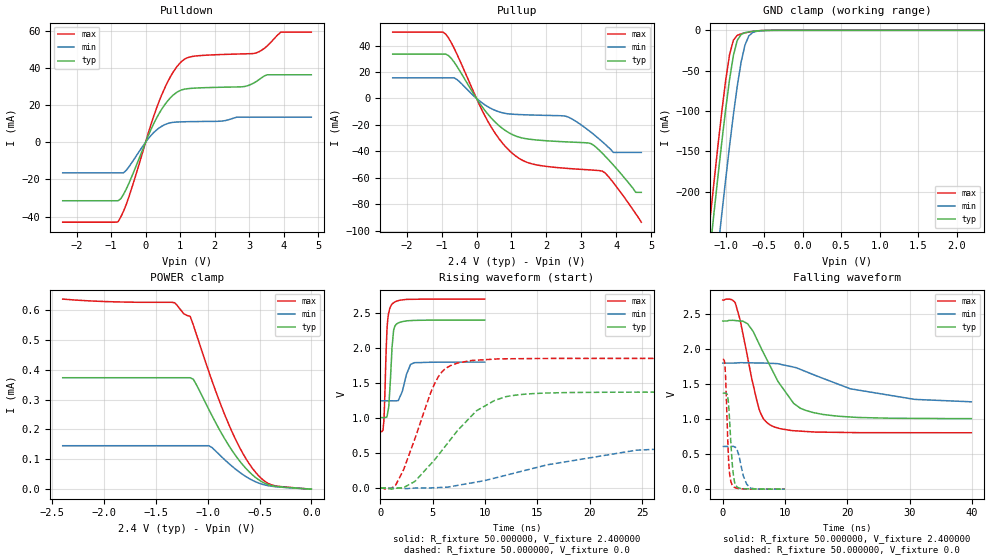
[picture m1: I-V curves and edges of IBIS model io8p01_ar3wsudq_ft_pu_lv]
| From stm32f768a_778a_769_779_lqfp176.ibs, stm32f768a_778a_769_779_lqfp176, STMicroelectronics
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|   Model io8p01_ar3wsudq_ft_pu_lv
[Model]  io8p01_ar3wsudq_ft_pu_lv
Model_type I/O
Polarity   Non-Inverting
Enable   Active-Low
Vinl =   0.720000V
Vinh =   1.680000V
Vmeas =  1.200000V
Cref =   50.000000pF
Rref =   100.000000M
Vref =   0.0V
C_comp   3.720900pF   3.684200pF   3.822900pF
[Temperature Range]   25.000000   0.125000k   -40.000000
[Pullup Reference]   2.400000V   1.800000V   2.700000V
[Pulldown Reference]   0.0V   0.0V   0.0V
[POWER Clamp Reference]   2.400000V   1.800000V   2.700000V
[GND Clamp Reference]   0.0V   0.0V   0.0V
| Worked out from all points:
|   slope of the pulldown table from 0 to 0.36 V, typ, clamps not added: 25 ohm
|   slope of the pullup table from 0 to 0.36 V, typ, clamps not added: 27.7 ohm
|   GND clamp passes 1 mA (typ) near -0.62 V on its own axis
|   rising waveform, R_fixture 50.000000, V_fixture 2.400000: 20-80 % time 330ps typ, 644ps min, 262ps max; typ from 1.01 V to 2.4 V
|   rising waveform, R_fixture 50.000000, V_fixture 0.0: 20-80 % time 4.73ns typ, 11.9ns min, 2.67ns max; typ from 0.001 V to 1.37 V
|   falling waveform, R_fixture 50.000000, V_fixture 2.400000: 20-80 % time 5.31ns typ, 12.6ns min, 2.7ns max; typ from 2.4 V to 1.01 V
|   falling waveform, R_fixture 50.000000, V_fixture 0.0: 20-80 % time 594ps typ, 1.03ns min, 462ps max; typ from 1.37 V to 0.001 V
[Pulldown]
|Voltage   I(typ)   I(min)   I(max)
-2.4V     -31.47mA   -16.45mA   -43.01mA
-800mV    -31.47mA   -16.45mA   -42.85mA
-480mV    -21.98mA   -13.17mA   -29.21mA
80mV      3.63mA     1.966mA    5.014mA
480mV     18.16mA    8.738mA    26.02mA
800mV     25.38mA    10.72mA    37.77mA
1.12V     28.53mA    11.02mA    44.6mA
2.8V      29.84mA    13.47mA    47.53mA
3.2V      32.6mA     13.47mA    48.03mA
3.52V     36.29mA    13.47mA    51.75mA
3.92V     36.29mA    13.47mA    59.26mA
4.8V      36.29mA    13.47mA    59.26mA
[Pullup]
|Voltage   I(typ)   I(min)   I(max)
-2.4V     33.5mA     15.56mA    50.21mA
-960mV    33.5mA     15.56mA    50.21mA
-560mV    24.27mA    14.3mA     33.51mA
320mV     -11.75mA   -6.207mA   -17.08mA
960mV     -26.47mA   -11.82mA   -40.02mA
1.52V     -30.88mA   -12.51mA   -49.05mA
2.56V     -32.88mA   -13.52mA   -52.9mA
3.28V     -34.25mA   -25.64mA   -54.17mA
3.6V      -41.44mA   -32.74mA   -55.02mA
3.92V     -50.46mA   -40.9mA    -63.78mA
4.56V     -71.1mA    -40.9mA    -87.26mA
4.72V     -71.1mA    -40.9mA    -93.7mA
[GND_clamp]
|Voltage   I(typ)   I(min)   I(max)
-2.4V     -1.43A     -1.515A    -1.399A
-1.25V    -315.9mA   -407.2mA   -278.2mA
-1.2V     -270.1mA   -361.3mA   -232.1mA
-1.15V    -225mA     -316mA     -186.8mA
-1.1V     -180.9mA   -271.3mA   -142.7mA
-1.05V    -138.2mA   -227.5mA   -100.5mA
-950mV    -61.14mA   -143.6mA   -30.43mA
-900mV    -31.23mA   -104.7mA   -12.14mA
-850mV    -12.49mA   -69.4mA    -6.221mA
-750mV    -2.898mA   -18.35mA   -3.18mA
-600mV    -750.2uA   -1.218mA   -738.3uA
2.35V     0A         0A         0A
[POWER_clamp]
|Voltage   I(typ)   I(min)   I(max)
-2.4V     373.1uA    145.5uA    636.5uA
-1.32V    373.1uA    145.5uA    624.2uA
-1.23V    373.1uA    145.5uA    587.2uA
-1.17V    373.1uA    145.5uA    579uA
-1.14V    368.3uA    145.5uA    550.7uA
-990mV    267.3uA    145.5uA    393.9uA
-810mV    153.6uA    90.29uA    227.7uA
-690mV    93.37uA    55.97uA    138.2uA
-570mV    48.37uA    29.94uA    70.44uA
-480mV    25.27uA    17.04uA    35.17uA
-390mV    12.49uA    10.18uA    15.16uA
0V        0A         0A         0A
[Ramp]
| variable   typ   min   max
dV/dt_r  0.82207/4.72862n   0.36540/11.89681n   1.11083/2.66726n
dV/dt_f  0.83604/5.30747n   0.32304/13.46437n   1.13706/2.70224n
R_load = 50.000000
[Rising Waveform]
R_fixture= 50.000000
V_fixture= 2.400000
V_fixture_min= 1.800000
V_fixture_max= 2.700000
|time   V(typ)   V(min)   V(max)
0s        1.007V     1.247V     805.8mV
340.3ps   1.007V     1.247V     952.4mV
640.6ps   1.02V      1.247V     2.264V
820.8ps   1.189V     1.247V     2.513V
1.081ns   1.885V     1.247V     2.619V
1.281ns   2.262V     1.246V     2.647V
1.822ns   2.365V     1.286V     2.683V
2.883ns   2.392V     1.763V     2.696V
3.263ns   2.395V     1.791V     2.697V
9.97ns    2.4V       1.8V       2.7V
[Rising Waveform]
R_fixture= 50.000000
V_fixture= 0.0
V_fixture_min= 0.0
V_fixture_max= 0.0
|time   V(typ)   V(min)   V(max)
0s        1.058mV    912.7uV    1.36mV
1.522ns   -1.796mV   978.9uV    58.52mV
3.283ns   94.32mV    755.9uV    696.3mV
5.205ns   407.6mV    5.629mV    1.497V
6.086ns   575.8mV    11.51mV    1.689V
7.367ns   820.7mV    38.96mV    1.785V
9.209ns   1.107V     87.48mV    1.827V
13.37ns   1.335V     236.1mV    1.849V
24.42ns   1.37V      541.3mV    1.852V
39.88ns   1.371V     610.2mV    1.852V
[Falling Waveform]
R_fixture= 50.000000
V_fixture= 2.400000
V_fixture_min= 1.800000
V_fixture_max= 2.700000
|time   V(typ)   V(min)   V(max)
0s        2.4V       1.8V       2.7V
2.002ns   2.407V     1.801V     2.664V
2.803ns   2.4V       1.805V     2.412V
4.004ns   2.36V      1.804V     1.877V
5.846ns   2.072V     1.801V     1.14V
7.688ns   1.744V     1.796V     913mV
11.37ns   1.226V     1.742V     834.9mV
14.49ns   1.095V     1.637V     817.6mV
20.5ns    1.031V     1.433V     808.8mV
39.88ns   1.007V     1.247V     805.8mV
[Falling Waveform]
R_fixture= 50.000000
V_fixture= 0.0
V_fixture_min= 0.0
V_fixture_max= 0.0
|time   V(typ)   V(min)   V(max)
0s        1.371V     610.2mV    1.852V
380.4ps   1.371V     610.2mV    1.736V
880.9ps   1.273V     610mV      544.5mV
1.121ns   955.6mV    609.7mV    211.5mV
1.481ns   430.2mV    610.4mV    67.59mV
1.762ns   167.4mV    610.2mV    34.19mV
2.122ns   52.66mV    594mV      18.53mV
3.323ns   8.052mV    186.9mV    5.117mV
4.484ns   4.244mV    15.81mV    2.894mV
9.97ns    1.058mV    912.7uV    1.36mV
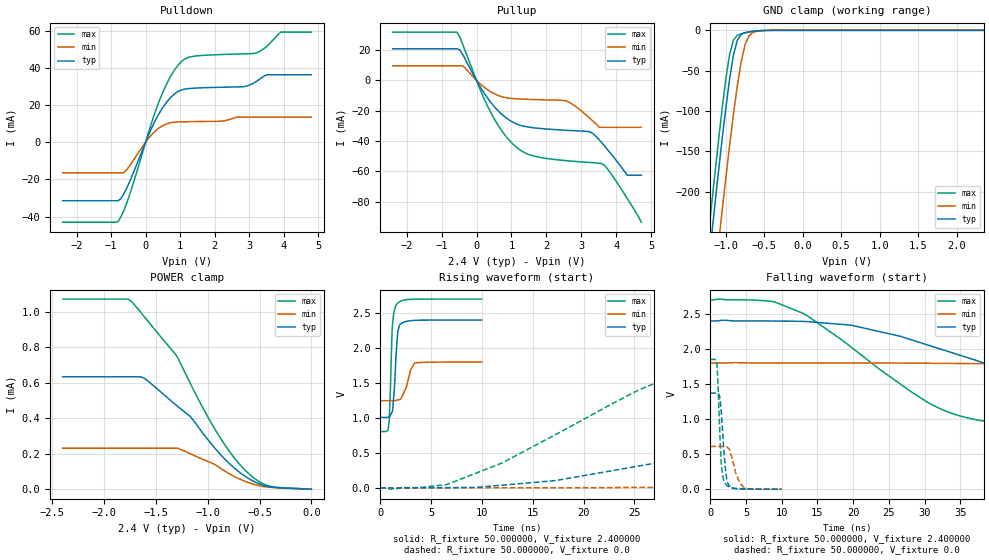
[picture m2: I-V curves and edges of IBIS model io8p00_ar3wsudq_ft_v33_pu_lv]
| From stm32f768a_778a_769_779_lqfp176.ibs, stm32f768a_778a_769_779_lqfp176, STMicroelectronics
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|   Model io8p00_ar3wsudq_ft_v33_pu_lv
[Model]  io8p00_ar3wsudq_ft_v33_pu_lv
Model_type I/O
Polarity   Non-Inverting
Enable   Active-Low
Vinl =   0.720000V
Vinh =   1.680000V
Vmeas =  1.200000V
Cref =   50.000000pF
Rref =   100.000000M
Vref =   0.0V
C_comp   3.737300pF   3.690400pF   3.817400pF
[Temperature Range]   25.000000   0.125000k   -40.000000
[Pullup Reference]   2.400000V   1.800000V   2.700000V
[Pulldown Reference]   0.0V   0.0V   0.0V
[POWER Clamp Reference]   2.400000V   1.800000V   2.700000V
[GND Clamp Reference]   0.0V   0.0V   0.0V
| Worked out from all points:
|   slope of the pulldown table from 0 to 0.36 V, typ, clamps not added: 25 ohm
|   slope of the pullup table from 0 to 0.36 V, typ, clamps not added: 27.7 ohm
|   GND clamp passes 1 mA (typ) near -0.62 V on its own axis
|   rising waveform, R_fixture 50.000000, V_fixture 2.400000: 20-80 % time 349ps typ, 697ps min, 262ps max; typ from 1.01 V to 2.4 V
|   rising waveform, R_fixture 50.000000, V_fixture 0.0: 20-80 % time 31ns typ, 81.8ns min, 14.6ns max; typ from 0.001 V to 1.37 V
|   falling waveform, R_fixture 50.000000, V_fixture 2.400000: 20-80 % time 28.8ns typ, 81.6ns min, 15.7ns max; typ from 2.4 V to 1.01 V
|   falling waveform, R_fixture 50.000000, V_fixture 0.0: 20-80 % time 599ps typ, 1.08ns min, 460ps max; typ from 1.37 V to 0.001 V
[Pulldown]
|Voltage   I(typ)   I(min)   I(max)
-2.4V     -31.47mA   -16.45mA   -43.01mA
-800mV    -31.47mA   -16.45mA   -42.85mA
-480mV    -21.98mA   -13.17mA   -29.21mA
80mV      3.63mA     1.966mA    5.014mA
480mV     18.16mA    8.738mA    26.02mA
800mV     25.38mA    10.72mA    37.77mA
1.12V     28.53mA    11.02mA    44.6mA
2.8V      29.84mA    13.47mA    47.53mA
3.2V      32.6mA     13.47mA    48.03mA
3.52V     36.3mA     13.47mA    51.75mA
3.92V     36.3mA     13.47mA    59.27mA
4.8V      36.3mA     13.47mA    59.27mA
[Pullup]
|Voltage   I(typ)   I(min)   I(max)
-2.4V     20.87mA    9.66mA     31.87mA
-560mV    20.87mA    9.66mA     31.87mA
-400mV    17.27mA    9.66mA     24.06mA
320mV     -11.75mA   -6.207mA   -17.08mA
640mV     -20.52mA   -10.1mA    -30.35mA
960mV     -26.47mA   -11.82mA   -40.02mA
1.52V     -30.88mA   -12.51mA   -49.05mA
2.56V     -32.88mA   -13.52mA   -52.9mA
3.28V     -34.25mA   -25.61mA   -54.17mA
3.6V      -41.44mA   -30.97mA   -55.02mA
4.32V     -62.54mA   -30.97mA   -77.98mA
4.72V     -62.54mA   -30.97mA   -93.5mA
[GND_clamp]
|Voltage   I(typ)   I(min)   I(max)
-2.4V     -1.437A    -1.518A    -1.411A
-1.25V    -315.9mA   -407.2mA   -278.2mA
-1.2V     -270.1mA   -361.3mA   -232.1mA
-1.15V    -225mA     -316mA     -186.8mA
-1.1V     -180.9mA   -271.3mA   -142.7mA
-1.05V    -138.2mA   -227.5mA   -100.5mA
-950mV    -61.14mA   -143.6mA   -30.43mA
-900mV    -31.23mA   -104.7mA   -12.14mA
-850mV    -12.49mA   -69.4mA    -6.221mA
-750mV    -2.898mA   -18.35mA   -3.18mA
-600mV    -750.2uA   -1.218mA   -738.3uA
2.35V     0A         0A         0A
[POWER_clamp]
|Voltage   I(typ)   I(min)   I(max)
-2.4V     634.4uA    230.9uA    1.073mA
-1.77V    634.4uA    230.9uA    1.073mA
-1.74V    634.4uA    230.9uA    1.062mA
-1.62V    628.7uA    230.9uA    979.3uA
-1.29V    467.4uA    230.9uA    743.1uA
-1.17V    410.9uA    200.6uA    599.2uA
-930mV    230.8uA    139uA      338.2uA
-780mV    138.4uA    83.46uA    204.6uA
-660mV    81.05uA    49.28uA    119.5uA
-540mV    39.7uA     25.07uA    57.27uA
-420mV    15.59uA    11.9uA     19.92uA
0V        0A         0A         0A
[Ramp]
| variable   typ   min   max
dV/dt_r  0.82201/30.92570n   0.36327/83.87425n   1.11083/14.60680n
dV/dt_f  0.83622/28.87659n   0.32652/81.83571n   1.13655/15.69998n
R_load = 50.000000
[Rising Waveform]
R_fixture= 50.000000
V_fixture= 2.400000
V_fixture_min= 1.800000
V_fixture_max= 2.700000
|time   V(typ)   V(min)   V(max)
0s        1.007V     1.247V     805.7mV
780.8ps   1.012V     1.247V     841.9mV
880.9ps   1.016V     1.247V     968.3mV
1.181ns   1.091V     1.247V     2.287V
1.381ns   1.402V     1.247V     2.533V
1.642ns   2.077V     1.254V     2.631V
1.722ns   2.228V     1.257V     2.642V
1.882ns   2.325V     1.262V     2.66V
3.383ns   2.395V     1.787V     2.698V
9.97ns    2.4V       1.8V       2.7V
[Rising Waveform]
R_fixture= 50.000000
V_fixture= 0.0
V_fixture_min= 0.0
V_fixture_max= 0.0
|time   V(typ)   V(min)   V(max)
0s        880.4uV    840.3uV    911.2uV
7.007ns   4.47mV     1.89mV     73.8mV
17.02ns   102.2mV    2.038mV    744.7mV
28.03ns   379.3mV    8.496mV    1.545V
34.53ns   558.8mV    15.84mV    1.716V
42.54ns   789.7mV    42.96mV    1.792V
59.56ns   1.173V     100.6mV    1.839V
79.58ns   1.316V     194.5mV    1.848V
153.2ns   1.369V     511.4mV    1.852V
249.2ns   1.371V     610.3mV    1.852V
[Falling Waveform]
R_fixture= 50.000000
V_fixture= 2.400000
V_fixture_min= 1.800000
V_fixture_max= 2.700000
|time   V(typ)   V(min)   V(max)
0s        2.4V       1.8V       2.7V
8.509ns   2.399V     1.8V       2.682V
13.01ns   2.395V     1.8V       2.508V
20.02ns   2.332V     1.8V       2.003V
31.03ns   2.038V     1.796V     1.204V
43.54ns   1.628V     1.776V     914.4mV
60.06ns   1.241V     1.72V      849.1mV
84.08ns   1.084V     1.587V     820.8mV
157.2ns   1.016V     1.326V     805.6mV
249.2ns   1.007V     1.247V     805.7mV
[Falling Waveform]
R_fixture= 50.000000
V_fixture= 0.0
V_fixture_min= 0.0
V_fixture_max= 0.0
|time   V(typ)   V(min)   V(max)
0s        1.371V     610.3mV    1.852V
900.9ps   1.372V     610.1mV    1.797V
1.101ns   1.368V     610mV      1.45V
1.502ns   1.152V     609.7mV    431.2mV
1.702ns   858.3mV    609.9mV    213.2mV
2.062ns   351.2mV    609.6mV    86.32mV
2.683ns   44.51mV    567.8mV    32.29mV
3.584ns   8.699mV    225.6mV    11.4mV
4.785ns   3.064mV    15.43mV    3.973mV
9.97ns    880.4uV    840.3uV    911.2uV
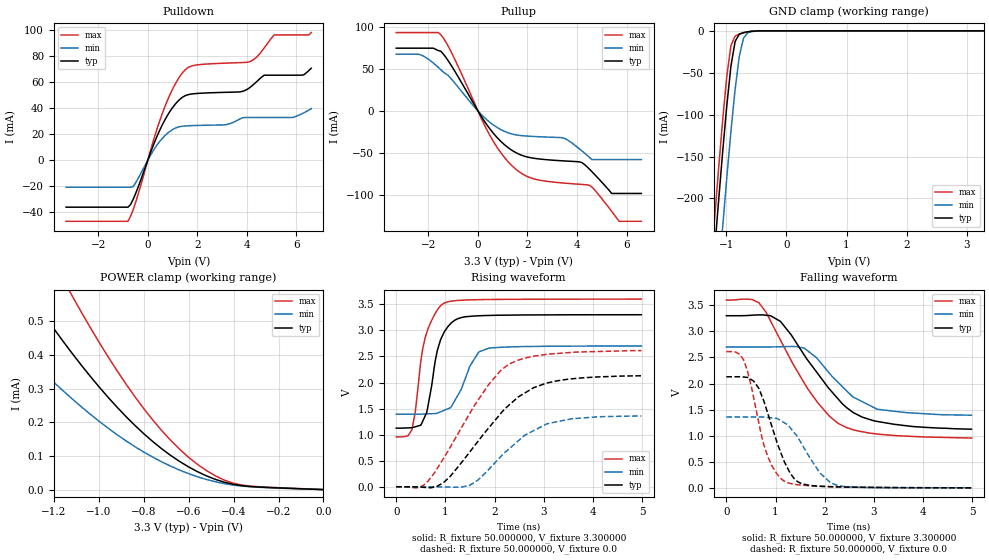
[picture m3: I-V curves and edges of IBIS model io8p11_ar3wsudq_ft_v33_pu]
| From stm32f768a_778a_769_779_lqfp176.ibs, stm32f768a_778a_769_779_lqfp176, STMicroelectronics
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|   Model io8p11_ar3wsudq_ft_v33_pu
[Model]  io8p11_ar3wsudq_ft_v33_pu
Model_type I/O
Polarity   Non-Inverting
Enable   Active-Low
Vinl =   0.990000V
Vinh =   2.310000V
Vmeas =  1.650000V
Cref =   30.000000pF
Rref =   100.000000M
Vref =   0.0V
C_comp   3.857500pF   3.760500pF   3.941700pF
[Temperature Range]   25.000000   0.125000k   -40.000000
[Pullup Reference]   3.300000V   2.700000V   3.600000V
[Pulldown Reference]   0.0V   0.0V   0.0V
[POWER Clamp Reference]   3.300000V   2.700000V   3.600000V
[GND Clamp Reference]   0.0V   0.0V   0.0V
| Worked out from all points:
|   slope of the pulldown table from 0 to 0.495 V, typ, clamps not added: 20.9 ohm
|   slope of the pullup table from 0 to 0.495 V, typ, clamps not added: 22.6 ohm
|   GND clamp passes 1 mA (typ) near -0.62 V on its own axis
|   POWER clamp passes 1 mA (typ) near -1.88 V on its own axis
|   rising waveform, R_fixture 50.000000, V_fixture 3.300000: 20-80 % time 276ps typ, 389ps min, 269ps max; typ from 1.12 V to 3.3 V
|   rising waveform, R_fixture 50.000000, V_fixture 0.0: 20-80 % time 1.16ns typ, 998ps min, 1.05ns max; typ from 0.001 V to 2.13 V
|   falling waveform, R_fixture 50.000000, V_fixture 3.300000: 20-80 % time 1.06ns typ, 878ps min, 1.03ns max; typ from 3.3 V to 1.12 V
|   falling waveform, R_fixture 50.000000, V_fixture 0.0: 20-80 % time 473ps typ, 562ps min, 410ps max; typ from 2.13 V to 0.001 V
[Pulldown]
|Voltage   I(typ)   I(min)   I(max)
-3.3V     -36.18mA   -20.77mA   -47.07mA
-800mV    -36.18mA   -20.77mA   -47.07mA
-600mV    -30.5mA    -20.52mA   -38.69mA
700mV     31.4mA     19.11mA    41.71mA
1.2V      45.15mA    25.37mA    61.75mA
1.6V      50.35mA    26.5mA     71.06mA
3.1V      52.28mA    27.26mA    74.76mA
4.1V      55.65mA    32.9mA     75.79mA
4.7V      65.5mA     32.9mA     86.49mA
5.1V      65.5mA     32.9mA     96.53mA
6.3V      65.8mA     36.47mA    96.53mA
6.6V      70.85mA    39.68mA    98.34mA
[Pullup]
|Voltage   I(typ)   I(min)   I(max)
-3.3V     74.6mA     67.42mA    93.17mA
-2.3V     74.6mA     66.59mA    93.17mA
-1.5V     71.1mA     49.01mA    90.67mA
-1V       50.41mA    35.45mA    65.35mA
500mV     -22.06mA   -14mA      -30.03mA
1.6V      -50.64mA   -28.81mA   -70.96mA
3.5V      -59.52mA   -32.72mA   -85.91mA
4.2V      -61.52mA   -47.6mA    -87.45mA
4.5V      -69.2mA    -55.15mA   -88.43mA
5.4V      -98.2mA    -57.9mA    -119.4mA
5.7V      -98.2mA    -57.9mA    -131.3mA
6.6V      -98.2mA    -57.9mA    -131.3mA
[GND_clamp]
|Voltage   I(typ)   I(min)   I(max)
-3.3V     -2.332A    -2.407A    -2.312A
-1.2V     -270.2mA   -361.4mA   -232.1mA
-1.13V    -207.3mA   -298.1mA   -169mA
-1.06V    -146.7mA   -236.2mA   -108.8mA
-990mV    -90.18mA   -176.4mA   -54.96mA
-920mV    -42.21mA   -120mA     -17.68mA
-850mV    -12.57mA   -69.47mA   -6.265mA
-780mV    -3.971mA   -30.01mA   -3.886mA
-710mV    -2.1mA     -8.615mA   -2.382mA
-640mV    -1.148mA   -2.283mA   -1.22mA
-570mV    -524uA     -821.5uA   -476.8uA
3.28V     0A         0A         0A
[POWER_clamp]
|Voltage   I(typ)   I(min)   I(max)
-3.28V    1.18mA     571.5uA    1.791mA
-3.08V    1.154mA    558.1uA    1.753mA
-1.84V    973.4uA    557.7uA    1.433mA
-1.32V    593.1uA    370.2uA    831.6uA
-1.28V    553.9uA    355.9uA    778.7uA
-1.12V    406uA      270.4uA    577.3uA
-960mV    275.2uA    183.2uA    395.9uA
-800mV    166.2uA    111.7uA    240.7uA
-680mV    101.4uA    69.6uA     146.3uA
-560mV    53.02uA    38.04uA    74.62uA
-360mV    11.49uA    10.29uA    13.1uA
0V        0A         0A         0A
[Ramp]
| variable   typ   min   max
dV/dt_r  1.26469/1.15951n   0.80727/0.99196n   1.56136/1.04842n
dV/dt_f  1.28070/1.04377n   0.77178/0.86640n   1.57114/1.02207n
R_load = 50.000000
[Rising Waveform]
R_fixture= 50.000000
V_fixture= 3.300000
V_fixture_min= 2.700000
V_fixture_max= 3.600000
|time   V(typ)   V(min)   V(max)
0s        1.125V     1.393V     955.5mV
320.3ps   1.133V     1.393V     1.096V
510.5ps   1.199V     1.394V     2.477V
650.7ps   1.574V     1.399V     3.042V
830.8ps   2.59V      1.411V     3.383V
971ps     2.96V      1.465V     3.52V
1.111ns   3.134V     1.522V     3.559V
1.682ns   3.28V      2.587V     3.589V
1.882ns   3.286V     2.659V     3.592V
4.985ns   3.3V       2.7V       3.599V
[Rising Waveform]
R_fixture= 50.000000
V_fixture= 0.0
V_fixture_min= 0.0
V_fixture_max= 0.0
|time   V(typ)   V(min)   V(max)
0s        1.299mV    1.125mV    1.756mV
550.6ps   -9.392mV   928uV      27.16mV
951ps     72.55mV    -2.714mV   528.7mV
1.491ns   662.9mV    27.15mV    1.4V
1.882ns   1.131V     332.1mV    1.964V
2.272ns   1.55V      709.6mV    2.337V
2.613ns   1.798V     987.3mV    2.466V
3.073ns   1.991V     1.211V     2.542V
3.564ns   2.07V      1.304V     2.577V
4.985ns   2.129V     1.36V      2.612V
[Falling Waveform]
R_fixture= 50.000000
V_fixture= 3.300000
V_fixture_min= 2.700000
V_fixture_max= 3.600000
|time   V(typ)   V(min)   V(max)
0s        3.3V       2.7V       3.599V
660.7ps   3.315V     2.7V       3.55V
810.8ps   3.309V     2.701V     3.363V
1.101ns   3.19V      2.705V     2.832V
1.582ns   2.549V     2.679V     2.015V
1.862ns   2.187V     2.463V     1.628V
2.272ns   1.705V     2.024V     1.237V
2.583ns   1.443V     1.74V      1.113V
3.073ns   1.273V     1.507V     1.032V
4.985ns   1.125V     1.393V     955.5mV
[Falling Waveform]
R_fixture= 50.000000
V_fixture= 0.0
V_fixture_min= 0.0
V_fixture_max= 0.0
|time   V(typ)   V(min)   V(max)
0s        2.129V     1.36V      2.612V
350.4ps   2.125V     1.359V     2.456V
510.5ps   2.073V     1.359V     1.935V
660.7ps   1.908V     1.358V     1.246V
860.9ps   1.374V     1.348V     562.4mV
1.191ns   478.8mV    1.242V     123.2mV
1.491ns   99.44mV    910mV      57.23mV
1.902ns   31.84mV    286.2mV    32.4mV
2.282ns   19.21mV    40.56mV    19.96mV
4.985ns   1.299mV    1.125mV    1.756mV
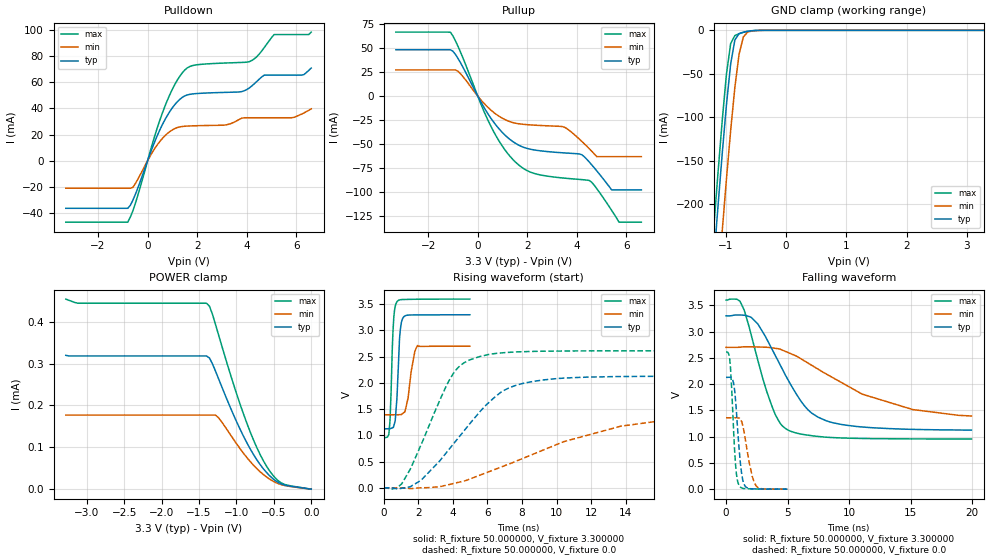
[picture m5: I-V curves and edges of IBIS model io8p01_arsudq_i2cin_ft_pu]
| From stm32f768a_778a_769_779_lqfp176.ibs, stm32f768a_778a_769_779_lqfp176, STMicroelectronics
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|   Model io8p01_arsudq_i2cin_ft_pu
[Model]  io8p01_arsudq_i2cin_ft_pu
Model_type I/O
Polarity   Non-Inverting
Enable   Active-Low
Vinl =   0.990000V
Vinh =   2.310000V
Vmeas =  1.650000V
Cref =   50.000000pF
Rref =   100.000000M
Vref =   0.0V
C_comp   2.280000pF   2.217100pF   2.355700pF
[Temperature Range]   25.000000   0.125000k   -40.000000
[Pullup Reference]   3.300000V   2.700000V   3.600000V
[Pulldown Reference]   0.0V   0.0V   0.0V
[POWER Clamp Reference]   3.300000V   2.700000V   3.600000V
[GND Clamp Reference]   0.0V   0.0V   0.0V
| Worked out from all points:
|   slope of the pulldown table from 0 to 0.495 V, typ, clamps not added: 20.9 ohm
|   slope of the pullup table from 0 to 0.495 V, typ, clamps not added: 22.6 ohm
|   GND clamp passes 1 mA (typ) near -0.62 V on its own axis
|   rising waveform, R_fixture 50.000000, V_fixture 3.300000: 20-80 % time 191ps typ, 342ps min, 164ps max; typ from 1.12 V to 3.3 V
|   rising waveform, R_fixture 50.000000, V_fixture 0.0: 20-80 % time 3.35ns typ, 6.92ns min, 2.1ns max; typ from 0.001 V to 2.13 V
|   falling waveform, R_fixture 50.000000, V_fixture 3.300000: 20-80 % time 3.18ns typ, 6.84ns min, 1.99ns max; typ from 3.3 V to 1.12 V
|   falling waveform, R_fixture 50.000000, V_fixture 0.0: 20-80 % time 434ps typ, 633ps min, 342ps max; typ from 2.13 V to 0.001 V
[Pulldown]
|Voltage   I(typ)   I(min)   I(max)
-3.3V     -36.46mA   -21.09mA   -47.09mA
-800mV    -36.46mA   -21.09mA   -47.09mA
-600mV    -30.5mA    -20.55mA   -38.69mA
700mV     31.4mA     19.11mA    41.71mA
1.2V      45.15mA    25.37mA    61.75mA
1.6V      50.35mA    26.5mA     71.06mA
3.1V      52.28mA    27.26mA    74.76mA
4.1V      55.64mA    32.87mA    75.8mA
4.7V      65.47mA    32.87mA    86.49mA
5.1V      65.47mA    32.87mA    96.56mA
6.2V      65.47mA    35.57mA    96.56mA
6.6V      70.92mA    39.71mA    98.46mA
[Pullup]
|Voltage   I(typ)   I(min)   I(max)
-3.3V     48.4mA     27.38mA    66.91mA
-1.1V     48.4mA     27.38mA    66.69mA
-700mV    35.09mA    23.45mA    46.29mA
500mV     -22.06mA   -14mA      -30.03mA
1.5V      -49.1mA    -28.3mA    -68.56mA
2.2V      -56.04mA   -30.32mA   -80.35mA
3.5V      -59.52mA   -32.65mA   -85.91mA
4.5V      -69.07mA   -55.13mA   -88.37mA
4.8V      -78.22mA   -63.4mA    -96.83mA
5.4V      -98.2mA    -63.4mA    -119.6mA
5.7V      -98.2mA    -63.4mA    -132mA
6.6V      -98.2mA    -63.4mA    -132mA
[GND_clamp]
|Voltage   I(typ)   I(min)   I(max)
-3.3V     -2.318A    -2.397A    -2.291A
-1.2V     -265.5mA   -356.1mA   -227.2mA
-1.13V    -202.6mA   -292.9mA   -164.1mA
-1.06V    -142.2mA   -231.2mA   -104.1mA
-990mV    -85.98mA   -171.6mA   -50.72mA
-920mV    -38.8mA    -115.5mA   -15.28mA
-850mV    -11.08mA   -65.6mA    -6.001mA
-780mV    -3.782mA   -27.42mA   -3.876mA
-710mV    -2.086mA   -7.69mA    -2.381mA
-640mV    -1.147mA   -2.118mA   -1.22mA
-570mV    -523.9uA   -798.4uA   -476.8uA
3.28V     0A         0A         0A
[POWER_clamp]
|Voltage   I(typ)   I(min)   I(max)
-3.28V    319.9uA    177.1uA    454.3uA
-3.12V    318.3uA    177.1uA    444.3uA
-1.4V     318.3uA    177.1uA    444.3uA
-1.36V    313.4uA    177.1uA    437.2uA
-1.28V    282.3uA    177.1uA    394.1uA
-1.24V    264.6uA    170.9uA    369.7uA
-920mV    131.9uA    89.35uA    187.2uA
-760mV    79.47uA    55.13uA    112.7uA
-640mV    48.78uA    35.04uA    68.06uA
-520mV    26.21uA    20.11uA    35uA
-400mV    12.52uA    10.81uA    14.88uA
0V        0A         0A         0A
[Ramp]
| variable   typ   min   max
dV/dt_r  1.27747/3.34646n   0.79953/6.93767n   1.56682/2.09411n
dV/dt_f  1.30134/3.17880n   0.73980/6.80234n   1.58700/1.99075n
R_load = 50.000000
[Rising Waveform]
R_fixture= 50.000000
V_fixture= 3.300000
V_fixture_min= 2.700000
V_fixture_max= 3.600000
|time   V(typ)   V(min)   V(max)
0s        1.125V     1.393V     955.6mV
300.3ps   1.127V     1.393V     1.025V
370.4ps   1.129V     1.393V     1.302V
500.5ps   1.143V     1.393V     2.661V
580.6ps   1.175V     1.393V     3.213V
760.8ps   1.678V     1.392V     3.542V
930.9ps   2.896V     1.395V     3.584V
1.161ns   3.261V     1.433V     3.591V
1.952ns   3.296V     2.713V     3.595V
4.985ns   3.3V       2.7V       3.599V
[Rising Waveform]
R_fixture= 50.000000
V_fixture= 0.0
V_fixture_min= 0.0
V_fixture_max= 0.0
|time   V(typ)   V(min)   V(max)
0s        1.447mV    1.248mV    1.816mV
1.041ns   -7.796mV   -483.2uV   74.96mV
2.162ns   143.5mV    824.5uV    820.3mV
3.844ns   758.6mV    67.51mV    2.08V
4.324ns   954.6mV    104.8mV    2.298V
4.965ns   1.215V     165.4mV    2.438V
6.767ns   1.819V     393.1mV    2.571V
8.208ns   2.002V     582.4mV    2.597V
13.69ns   2.122V     1.173V     2.612V
19.94ns   2.129V     1.36V      2.612V
[Falling Waveform]
R_fixture= 50.000000
V_fixture= 3.300000
V_fixture_min= 2.700000
V_fixture_max= 3.600000
|time   V(typ)   V(min)   V(max)
0s        3.3V       2.7V       3.599V
880.9ps   3.315V     2.7V       3.615V
1.441ns   3.311V     2.71V      3.426V
2.563ns   3.15V      2.707V     2.472V
3.684ns   2.688V     2.692V     1.609V
4.965ns   2.111V     2.608V     1.136V
6.647ns   1.514V     2.402V     1.029V
8.488ns   1.277V     2.147V     985mV
15.18ns   1.139V     1.516V     957.5mV
19.94ns   1.125V     1.393V     955.6mV
[Falling Waveform]
R_fixture= 50.000000
V_fixture= 0.0
V_fixture_min= 0.0
V_fixture_max= 0.0
|time   V(typ)   V(min)   V(max)
0s        2.129V     1.36V      2.612V
300.3ps   2.131V     1.359V     2.469V
450.5ps   2.12V      1.359V     1.945V
620.6ps   2.013V     1.359V     1.077V
830.8ps   1.515V     1.361V     319.5mV
1.041ns   823.8mV    1.354V     81.83mV
1.451ns   101.8mV    1.115V     13.34mV
1.872ns   14.37mV    520.6mV    7.459mV
2.422ns   5.905mV    72.28mV    4.505mV
4.985ns   1.447mV    1.248mV    1.816mV
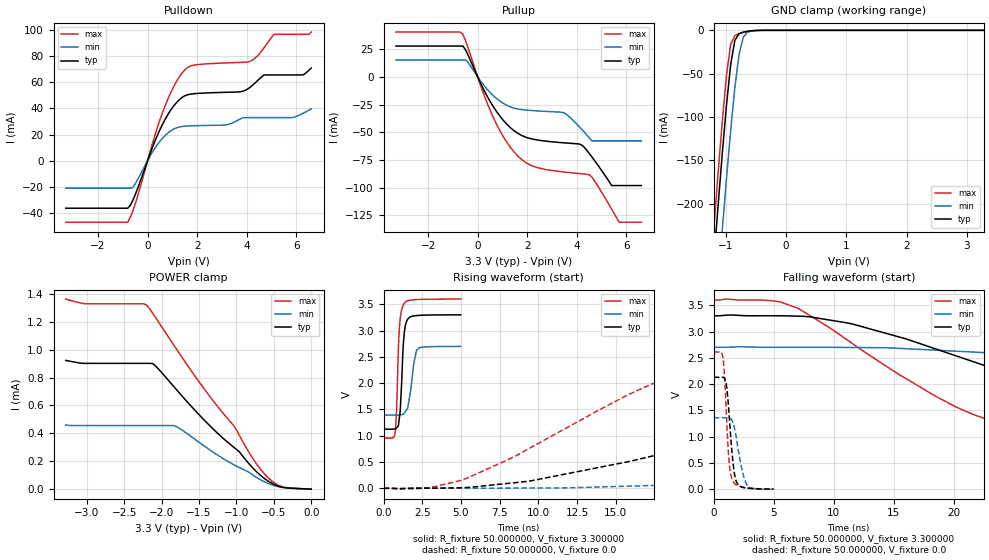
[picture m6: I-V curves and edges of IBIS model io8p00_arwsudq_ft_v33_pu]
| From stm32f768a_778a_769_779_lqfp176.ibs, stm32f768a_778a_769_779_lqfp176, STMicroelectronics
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|   Model io8p00_arwsudq_ft_v33_pu
[Model]  io8p00_arwsudq_ft_v33_pu
Model_type I/O
Polarity   Non-Inverting
Enable   Active-Low
Vinl =   0.990000V
Vinh =   2.310000V
Vmeas =  1.650000V
Cref =   50.000000pF
Rref =   100.000000M
Vref =   0.0V
C_comp   2.911600pF   2.826500pF   2.975800pF
[Temperature Range]   25.000000   0.125000k   -40.000000
[Pullup Reference]   3.300000V   2.700000V   3.600000V
[Pulldown Reference]   0.0V   0.0V   0.0V
[POWER Clamp Reference]   3.300000V   2.700000V   3.600000V
[GND Clamp Reference]   0.0V   0.0V   0.0V
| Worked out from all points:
|   slope of the pulldown table from 0 to 0.495 V, typ, clamps not added: 20.9 ohm
|   slope of the pullup table from 0 to 0.495 V, typ, clamps not added: 22.6 ohm
|   GND clamp passes 1 mA (typ) near -0.62 V on its own axis
|   rising waveform, R_fixture 50.000000, V_fixture 3.300000: 20-80 % time 219ps typ, 367ps min, 187ps max; typ from 1.12 V to 3.3 V
|   rising waveform, R_fixture 50.000000, V_fixture 0.0: 20-80 % time 19.7ns typ, 51.7ns min, 10.4ns max; typ from 0.001 V to 2.13 V
|   falling waveform, R_fixture 50.000000, V_fixture 3.300000: 20-80 % time 18.6ns typ, 38.6ns min, 11.3ns max; typ from 3.3 V to 1.12 V
|   falling waveform, R_fixture 50.000000, V_fixture 0.0: 20-80 % time 462ps typ, 672ps min, 373ps max; typ from 2.13 V to 0.001 V
[Pulldown]
|Voltage   I(typ)   I(min)   I(max)
-3.3V     -36.38mA   -21.07mA   -47.09mA
-800mV    -36.38mA   -21.07mA   -47.09mA
-600mV    -30.5mA    -20.54mA   -38.69mA
700mV     31.4mA     19.11mA    41.71mA
1.2V      45.15mA    25.37mA    61.75mA
1.6V      50.35mA    26.5mA     71.06mA
3.1V      52.28mA    27.26mA    74.76mA
4.1V      55.65mA    32.94mA    75.79mA
4.7V      65.59mA    32.94mA    86.49mA
5.1V      65.59mA    32.94mA    96.67mA
6.3V      65.82mA    36.48mA    96.67mA
6.6V      70.87mA    39.69mA    98.38mA
[Pullup]
|Voltage   I(typ)   I(min)   I(max)
-3.3V     28mA       15.42mA    40.61mA
-700mV    28mA       15.42mA    40.61mA
-400mV    20.3mA     13.47mA    26.92mA
600mV     -25.77mA   -16.23mA   -35.13mA
1.6V      -50.64mA   -28.8mA    -70.96mA
2.3V      -56.49mA   -30.48mA   -81.16mA
3.5V      -59.52mA   -32.65mA   -85.91mA
4.2V      -61.45mA   -47.47mA   -87.45mA
4.5V      -69.09mA   -55.01mA   -88.4mA
5.4V      -98.1mA    -57.7mA    -119.3mA
5.7V      -98.1mA    -57.7mA    -131.2mA
6.6V      -98.1mA    -57.7mA    -131.2mA
[GND_clamp]
|Voltage   I(typ)   I(min)   I(max)
-3.3V     -2.321A    -2.397A    -2.298A
-1.2V     -266.4mA   -356.3mA   -229.4mA
-1.13V    -203.6mA   -293.1mA   -166.3mA
-1.06V    -143.2mA   -231.4mA   -106.2mA
-990mV    -86.95mA   -171.8mA   -52.65mA
-920mV    -39.66mA   -115.8mA   -16.36mA
-850mV    -11.49mA   -65.84mA   -6.11mA
-780mV    -3.834mA   -27.59mA   -3.88mA
-710mV    -2.09mA    -7.753mA   -2.381mA
-640mV    -1.147mA   -2.129mA   -1.22mA
-570mV    -523.9uA   -800uA     -476.8uA
3.28V     0A         0A         0A
[POWER_clamp]
|Voltage   I(typ)   I(min)   I(max)
-3.28V    922.4uA    459.4uA    1.362mA
-3.04V    901.4uA    455.8uA    1.329mA
-2.2V     901.4uA    455.8uA    1.319mA
-2.08V    882.2uA    455.8uA    1.23mA
-1.8V     712.4uA    448.4uA    1.003mA
-1.4V     478.6uA    298uA      696.5uA
-1.04V    302.3uA    176.6uA    458.6uA
-800mV    163uA      108.7uA    236.3uA
-640mV    82.53uA    56.82uA    118.4uA
-520mV    40.35uA    29.6uA     55.89uA
-400mV    15.52uA    13.26uA    18.69uA
0V        0A         0A         0A
[Ramp]
| variable   typ   min   max
dV/dt_r  1.27729/19.66632n   0.81669/51.90389n   1.56688/10.39629n
dV/dt_f  1.30554/18.56173n   0.78450/38.78000n   1.58713/11.31272n
R_load = 50.000000
[Rising Waveform]
R_fixture= 50.000000
V_fixture= 3.300000
V_fixture_min= 2.700000
V_fixture_max= 3.600000
|time   V(typ)   V(min)   V(max)
0s        1.125V     1.393V     954.7mV
760.8ps   1.133V     1.393V     1.094V
840.8ps   1.154V     1.393V     1.534V
951ps     1.189V     1.393V     2.649V
1.011ns   1.327V     1.395V     3.029V
1.071ns   1.471V     1.398V     3.229V
1.301ns   2.851V     1.419V     3.508V
1.552ns   3.215V     1.523V     3.566V
2.132ns   3.286V     2.628V     3.59V
4.985ns   3.3V       2.7V       3.6V
[Rising Waveform]
R_fixture= 50.000000
V_fixture= 0.0
V_fixture_min= 0.0
V_fixture_max= 0.0
|time   V(typ)   V(min)   V(max)
0s        1.089mV    1.043mV    1.137mV
3.003ns   3.647mV    2.472mV    13.9mV
5.506ns   17.72mV    2.828mV    208.6mV
19.02ns   730mV      66.65mV    2.162V
30.53ns   1.503V     233.5mV    2.53V
37.54ns   1.836V     348.4mV    2.568V
45.55ns   1.985V     497.5mV    2.597V
72.07ns   2.103V     973.7mV    2.612V
96.6ns    2.122V     1.196V     2.613V
249.2ns   2.13V      1.36V      2.613V
[Falling Waveform]
R_fixture= 50.000000
V_fixture= 3.300000
V_fixture_min= 2.700000
V_fixture_max= 3.600000
|time   V(typ)   V(min)   V(max)
0s        3.3V       2.7V       3.6V
7.007ns   3.292V     2.7V       3.444V
11.51ns   3.146V     2.697V     2.778V
18.52ns   2.667V     2.645V     1.766V
22.52ns   2.358V     2.599V     1.349V
34.03ns   1.585V     2.37V      1.05V
49.05ns   1.251V     2.009V     990.6mV
65.07ns   1.18V      1.698V     966.3mV
86.59ns   1.148V     1.526V     958.5mV
249.2ns   1.125V     1.393V     954.7mV
[Falling Waveform]
R_fixture= 50.000000
V_fixture= 0.0
V_fixture_min= 0.0
V_fixture_max= 0.0
|time   V(typ)   V(min)   V(max)
0s        2.13V      1.36V      2.613V
640.6ps   2.13V      1.36V      2.603V
790.8ps   2.126V     1.359V     2.464V
1.001ns   2.048V     1.359V     1.673V
1.221ns   1.593V     1.357V     692.2mV
1.361ns   1.157V     1.346V     348.1mV
1.552ns   624.9mV    1.291V     174.2mV
1.902ns   137.2mV    945.6mV    78.85mV
2.713ns   22.78mV    103.4mV    27.58mV
4.985ns   1.089mV    1.043mV    1.137mV
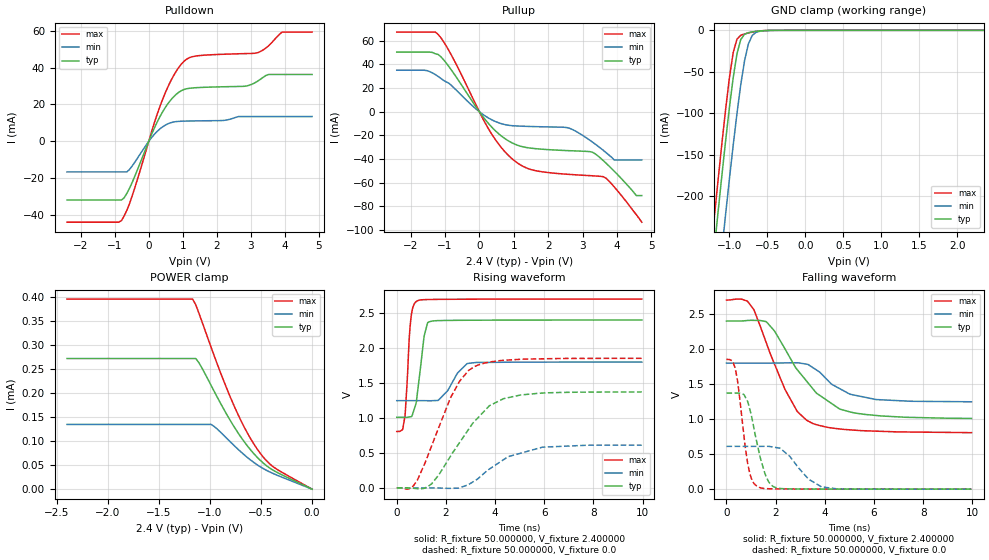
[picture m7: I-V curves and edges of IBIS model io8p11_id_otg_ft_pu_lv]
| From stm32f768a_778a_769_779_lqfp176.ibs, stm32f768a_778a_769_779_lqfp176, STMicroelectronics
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|   Model io8p11_id_otg_ft_pu_lv
[Model]  io8p11_id_otg_ft_pu_lv
Model_type I/O
Polarity   Non-Inverting
Enable   Active-Low
Vinl =   0.720000V
Vinh =   1.680000V
Vmeas =  1.200000V
Cref =   30.000000pF
Rref =   100.000000M
Vref =   0.0V
C_comp   2.229800pF   2.169700pF   2.325100pF
[Temperature Range]   25.000000   0.125000k   -40.000000
[Pullup Reference]   2.400000V   1.800000V   2.700000V
[Pulldown Reference]   0.0V   0.0V   0.0V
[POWER Clamp Reference]   2.400000V   1.800000V   2.700000V
[GND Clamp Reference]   0.0V   0.0V   0.0V
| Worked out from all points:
|   slope of the pulldown table from 0 to 0.36 V, typ, clamps not added: 25 ohm
|   slope of the pullup table from 0 to 0.36 V, typ, clamps not added: 27.7 ohm
|   GND clamp passes 1 mA (typ) near -0.62 V on its own axis
|   rising waveform, R_fixture 50.000000, V_fixture 2.400000: 20-80 % time 281ps typ, 622ps min, 182ps max; typ from 1.01 V to 2.4 V
|   rising waveform, R_fixture 50.000000, V_fixture 0.0: 20-80 % time 1.69ns typ, 1.7ns min, 1.32ns max; typ from 0.004 V to 1.37 V
|   falling waveform, R_fixture 50.000000, V_fixture 2.400000: 20-80 % time 1.83ns typ, 1.3ns min, 1.38ns max; typ from 2.4 V to 1.01 V
|   falling waveform, R_fixture 50.000000, V_fixture 0.0: 20-80 % time 539ps typ, 931ps min, 387ps max; typ from 1.37 V to 0.004 V
[Pulldown]
|Voltage   I(typ)   I(min)   I(max)
-2.4V     -31.73mA   -16.51mA   -43.74mA
-800mV    -31.73mA   -16.51mA   -42.87mA
-480mV    -21.97mA   -13.17mA   -29.21mA
80mV      3.63mA     1.966mA    5.014mA
480mV     18.15mA    8.737mA    26.02mA
800mV     25.37mA    10.72mA    37.77mA
1.12V     28.53mA    11.02mA    44.6mA
2.8V      29.84mA    13.46mA    47.53mA
3.2V      32.6mA     13.46mA    48.03mA
3.52V     36.23mA    13.46mA    51.75mA
3.92V     36.23mA    13.46mA    59.19mA
4.8V      36.23mA    13.46mA    59.19mA
[Pullup]
|Voltage   I(typ)   I(min)   I(max)
-2.4V     50.44mA    35.08mA    67.34mA
-1.52V    50.44mA    34.74mA    67.34mA
-1.2V     48.48mA    29.88mA    65.49mA
320mV     -11.75mA   -6.206mA   -17.08mA
1.04V     -27.53mA   -11.97mA   -41.9mA
1.6V      -31.13mA   -12.57mA   -49.62mA
2.56V     -32.87mA   -13.48mA   -52.89mA
3.28V     -34.17mA   -25.51mA   -54.16mA
3.6V      -41.29mA   -32.6mA    -54.95mA
3.92V     -50.3mA    -40.8mA    -63.6mA
4.56V     -70.9mA    -40.8mA    -87.05mA
4.72V     -70.9mA    -40.8mA    -93.4mA
[GND_clamp]
|Voltage   I(typ)   I(min)   I(max)
-2.4V     -1.424A    -1.508A    -1.393A
-1.25V    -311.2mA   -401.9mA   -273.3mA
-1.2V     -265.4mA   -356.1mA   -227.2mA
-1.15V    -220.4mA   -310.8mA   -181.9mA
-1.1V     -176.3mA   -266.2mA   -137.9mA
-1.05V    -133.8mA   -222.5mA   -95.88mA
-950mV    -57.31mA   -138.9mA   -26.99mA
-900mV    -28.28mA   -100.4mA   -10.61mA
-850mV    -11.02mA   -65.55mA   -5.978mA
-750mV    -2.847mA   -16.51mA   -3.192mA
-600mV    -755.4uA   -1.17mA    -743.6uA
2.35V     0A         0A         0A
[POWER_clamp]
|Voltage   I(typ)   I(min)   I(max)
-2.4V     272.5uA    135uA      396.5uA
-1.17V    272.5uA    135uA      396.5uA
-1.14V    272.5uA    135uA      384.7uA
-1.11V    264.2uA    135uA      368uA
-990mV    216.8uA    135uA      296.5uA
-870mV    168.8uA    113.3uA    228.2uA
-750mV    125.6uA    88.19uA    167.1uA
-660mV    97.6uA     70.82uA    127.5uA
-570mV    73.91uA    55.62uA    94.12uA
-480mV    54.73uA    43.14uA    67.37uA
-390mV    40.65uA    33.48uA    48.23uA
0V        0A         0A         0A
[Ramp]
| variable   typ   min   max
dV/dt_r  0.82153/1.68911n   0.36481/1.68583n   1.11056/1.32240n
dV/dt_f  0.82950/1.81907n   0.33138/1.30083n   1.13305/1.37845n
R_load = 50.000000
[Rising Waveform]
R_fixture= 50.000000
V_fixture= 2.400000
V_fixture_min= 1.800000
V_fixture_max= 2.700000
|time   V(typ)   V(min)   V(max)
0s        1.011V     1.249V     809.2mV
240.2ps   1.011V     1.249V     836.9mV
340.3ps   1.011V     1.249V     1.043V
500.5ps   1.015V     1.249V     2.09V
580.6ps   1.02V      1.249V     2.436V
840.8ps   1.358V     1.249V     2.674V
1.121ns   2.181V     1.249V     2.691V
1.361ns   2.379V     1.248V     2.693V
2.883ns   2.397V     1.78V      2.697V
9.97ns    2.4V       1.8V       2.699V
[Rising Waveform]
R_fixture= 50.000000
V_fixture= 0.0
V_fixture_min= 0.0
V_fixture_max= 0.0
|time   V(typ)   V(min)   V(max)
0s        3.745mV    3.286mV    4.323mV
680.7ps   -1.614mV   3.272mV    34.09mV
1.421ns   62.42mV    3.32mV     605.2mV
2.202ns   464.2mV    -2.565mV   1.3V
2.563ns   653.8mV    7.148mV    1.53V
3.163ns   952.8mV    102.8mV    1.735V
3.764ns   1.174V     271.4mV    1.799V
4.344ns   1.277V     406mV      1.825V
5.926ns   1.357V     585mV      1.846V
9.97ns    1.373V     613.5mV    1.853V
[Falling Waveform]
R_fixture= 50.000000
V_fixture= 2.400000
V_fixture_min= 1.800000
V_fixture_max= 2.700000
|time   V(typ)   V(min)   V(max)
0s        2.4V       1.8V       2.699V
620.6ps   2.401V     1.8V       2.711V
1.101ns   2.41V      1.8V       2.569V
1.622ns   2.391V     1.8V       2.089V
2.382ns   2.003V     1.803V     1.424V
2.883ns   1.706V     1.805V     1.11V
3.283ns   1.534V     1.784V     981.5mV
3.664ns   1.372V     1.702V     922.8mV
5.065ns   1.101V     1.354V     848mV
9.97ns    1.011V     1.249V     809.2mV
[Falling Waveform]
R_fixture= 50.000000
V_fixture= 0.0
V_fixture_min= 0.0
V_fixture_max= 0.0
|time   V(typ)   V(min)   V(max)
0s        1.373V     613.5mV    1.853V
360.4ps   1.373V     613.5mV    1.721V
460.5ps   1.373V     613.5mV    1.526V
720.7ps   1.348V     613.4mV    737.1mV
961ps     1.128V     613.2mV    212.4mV
1.301ns   568.4mV    613.2mV    34.17mV
1.702ns   117.8mV    614.3mV    9.754mV
2.102ns   17.12mV    592.2mV    7.105mV
3.884ns   4.994mV    34.37mV    5.145mV
9.97ns    3.745mV    3.286mV    4.323mV
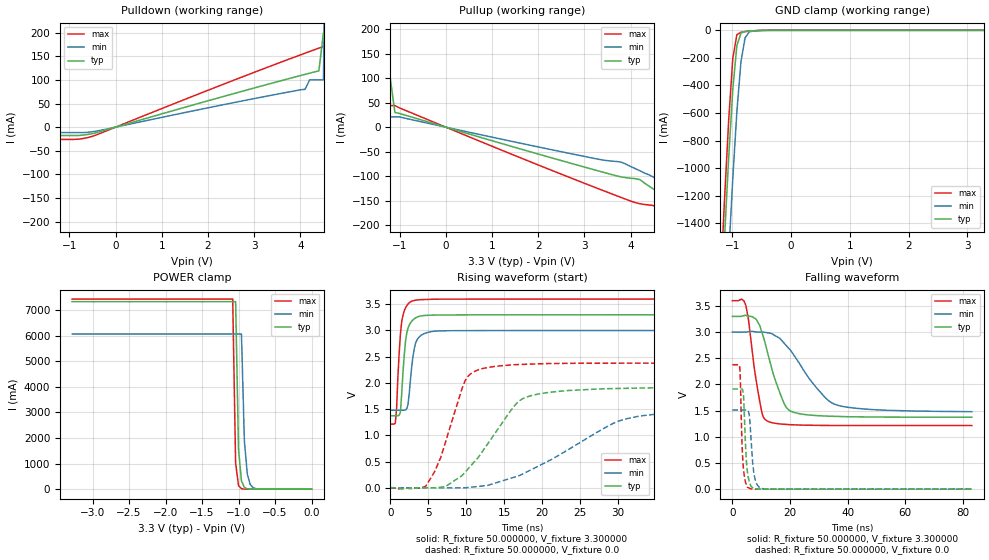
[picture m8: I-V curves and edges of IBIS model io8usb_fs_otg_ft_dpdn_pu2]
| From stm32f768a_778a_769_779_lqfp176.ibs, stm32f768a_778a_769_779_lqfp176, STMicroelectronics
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|   Model io8usb_fs_otg_ft_dpdn_pu2
[Model]  io8usb_fs_otg_ft_dpdn_pu2
Model_type I/O
Polarity   Non-Inverting
Enable   Active-Low
Vinl =   0.990000V
Vinh =   2.310000V
Vmeas =  1.650000V
Cref =   50.000000pF
Rref =   100.000000M
Vref =   0.0V
C_comp   8.255900pF   7.991100pF   8.650600pF
[Temperature Range]   25.000000   0.125000k   -40.000000
[Pullup Reference]   3.300000V   3.000000V   3.600000V
[Pulldown Reference]   0.0V   0.0V   0.0V
[POWER Clamp Reference]   3.300000V   3.000000V   3.600000V
[GND Clamp Reference]   0.0V   0.0V   0.0V
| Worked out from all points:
|   slope of the pulldown table from 0 to 0.495 V, typ, clamps not added: 35.4 ohm
|   slope of the pullup table from 0 to 0.495 V, typ, clamps not added: 36 ohm
|   GND clamp passes 1 mA (typ) near -0.52 V on its own axis
|   POWER clamp passes 1 mA (typ) near -0.81 V on its own axis
|   rising waveform, R_fixture 50.000000, V_fixture 3.300000: 20-80 % time 643ps typ, 746ps min, 588ps max; typ from 1.37 V to 3.3 V
|   rising waveform, R_fixture 50.000000, V_fixture 0.0: 20-80 % time 5.81ns typ, 11.1ns min, 3.15ns max; typ from 0 V to 1.91 V
|   falling waveform, R_fixture 50.000000, V_fixture 3.300000: 20-80 % time 6.32ns typ, 12.2ns min, 3.61ns max; typ from 3.3 V to 1.37 V
|   falling waveform, R_fixture 50.000000, V_fixture 0.0: 20-80 % time 1.03ns typ, 1.29ns min, 862ps max; typ from 1.91 V to 0 V
[Pulldown]
|Voltage   I(typ)   I(min)   I(max)
-3.3V     -181mA     -11.57mA   -221mA
-3.2V     -137mA     -11.57mA   -216mA
-2.9V     -124mA     -11.57mA   -200mA
-2.8V     -17.71mA   -11.57mA   -25.94mA
-600mV    -15.43mA   -10.85mA   -22.06mA
4.1V      111.6mA    80mA       156.4mA
4.4V      119mA      100mA      167.2mA
4.5V      200mA      100mA      170.7mA
4.6V      200mA      1A         174.2mA
4.8V      1A         1A         200mA
5.4V      1A         1A         1A
6.6V      1A         1A         1A
[Pullup]
|Voltage   I(typ)   I(min)   I(max)
-3.3V     1A         1A         1A
-1.9V     1A         1A         1A
-1.8V     100mA      1A         1A
-1.7V     100mA      1A         100mA
-1.6V     100mA      1A         100mA
-1.5V     100mA      21mA       100mA
-1.3V     100mA      21mA       100mA
-1.2V     100mA      21mA       44mA
-1.1V     30mA       21mA       44mA
4.2V      -107.2mA   -89.1mA    -156.5mA
5V        -156.8mA   -125mA     -203.2mA
6.6V      -223mA     -162mA     -321mA
[GND_clamp]
|Voltage   I(typ)   I(min)   I(max)
-3.3V     -9.433A    -9.435A    -9.911A
-1.2V     -2.116A    -2.846A    -1.847A
-1.13V    -1.505A    -2.23A     -1.23A
-1.06V    -930.4mA   -1.637A    -658.9mA
-990mV    -432.7mA   -1.08A     -207.3mA
-920mV    -110.5mA   -590.3mA   -31.59mA
-850mV    -19.84mA   -226.8mA   -13.66mA
-780mV    -8.32mA    -54.05mA   -9.516mA
-710mV    -5.29mA    -11.97mA   -6.271mA
-640mV    -3.236mA   -4.296mA   -3.584mA
3.28V     0A         0A         0A
[POWER_clamp]
|Voltage   I(typ)   I(min)   I(max)
-3.28V    7.328A     6.064A     7.43A
-1.08V    7.328A     6.064A     7.43A
-1.04V    7.328A     6.064A     1.015A
-1V       1.545A     6.064A     138.6mA
-960mV    325.6mA    6.064A     18.93mA
-920mV    68.64mA    1.89A      2.585mA
-880mV    14.47mA    589mA      353uA
-840mV    3.05mA     183.6mA    105.9uA
-800mV    642.9uA    57.21mA    105.9uA
-720mV    28.59uA    5.557mA    105.9uA
0V        0A         0A         0A
[Ramp]
| variable   typ   min   max
dV/dt_r  1.14807/5.79931n   0.90697/11.11583n   1.42586/3.14175n
dV/dt_f  1.15530/6.31678n   0.91044/12.20870n   1.43058/3.60437n
R_load = 50.000000
[Rising Waveform]
R_fixture= 50.000000
V_fixture= 3.300000
V_fixture_min= 3.000000
V_fixture_max= 3.600000
|time   V(typ)   V(min)   V(max)
0s        1.374V     1.479V     1.215V
667.3ps   1.374V     1.479V     1.235V
834.2ps   1.374V     1.479V     1.52V
1.001ns   1.374V     1.479V     2.104V
1.335ns   1.444V     1.479V     2.93V
1.668ns   2.192V     1.479V     3.29V
2.169ns   2.951V     1.508V     3.472V
3.337ns   3.24V      2.762V     3.578V
6.673ns   3.295V     2.993V     3.598V
83.08ns   3.3V       3V         3.6V
[Rising Waveform]
R_fixture= 50.000000
V_fixture= 0.0
V_fixture_min= 0.0
V_fixture_max= 0.0
|time   V(typ)   V(min)   V(max)
0s        158.5uV    83.46uV    305.9uV
4.671ns   -1.871mV   -1.413mV   29.69mV
6.673ns   11.2mV     -667.9uV   587.9mV
10.01ns   321.3mV    942.2uV    2.082V
12.85ns   838.7mV    45.69mV    2.294V
16.35ns   1.56V      202.4mV    2.348V
17.85ns   1.724V     291.9mV    2.356V
29.36ns   1.892V     1.228V     2.377V
33.37ns   1.903V     1.376V     2.377V
83.08ns   1.914V     1.512V     2.377V
[Falling Waveform]
R_fixture= 50.000000
V_fixture= 3.300000
V_fixture_min= 3.000000
V_fixture_max= 3.600000
|time   V(typ)   V(min)   V(max)
0s        3.3V       3V         3.6V
4.671ns   3.321V     3V         3.511V
9.676ns   3.095V     3V         1.623V
10.68ns   2.921V     2.999V     1.386V
12.18ns   2.615V     2.987V     1.3V
17.68ns   1.671V     2.805V     1.241V
21.52ns   1.464V     2.545V     1.229V
29.2ns    1.406V     1.937V     1.219V
36.04ns   1.39V      1.611V     1.216V
83.08ns   1.374V     1.479V     1.215V
[Falling Waveform]
R_fixture= 50.000000
V_fixture= 0.0
V_fixture_min= 0.0
V_fixture_max= 0.0
|time   V(typ)   V(min)   V(max)
0s        1.914V     1.512V     2.377V
2.503ns   1.914V     1.512V     2.349V
2.669ns   1.914V     1.512V     2.257V
3.337ns   1.916V     1.512V     889.9mV
3.67ns    1.875V     1.512V     513.2mV
4.838ns   560.2mV    1.512V     91.38mV
6.173ns   95.96mV    1.222V     10.07mV
7.508ns   13mV       292.5mV    2.821mV
9.676ns   2.221mV    20.28mV    959.5uV
83.08ns   158.5uV    83.46uV    305.9uV
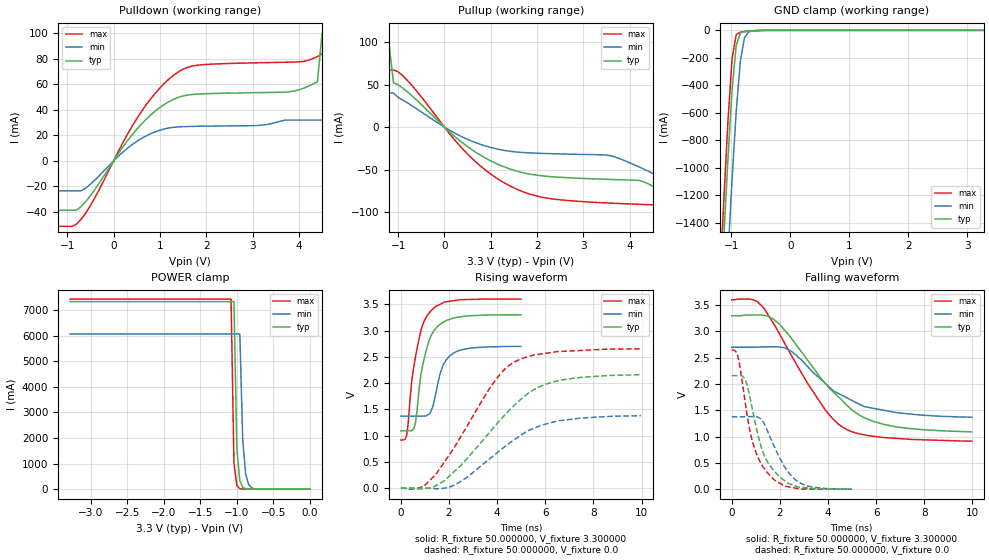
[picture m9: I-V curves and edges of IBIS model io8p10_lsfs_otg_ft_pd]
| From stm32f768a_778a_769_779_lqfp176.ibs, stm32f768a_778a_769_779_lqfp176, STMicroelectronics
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|   Model io8p10_lsfs_otg_ft_pd
[Model]  io8p10_lsfs_otg_ft_pd
Model_type I/O
Polarity   Non-Inverting
Enable   Active-Low
Vinl =   0.990000V
Vinh =   2.310000V
Vmeas =  1.650000V
Cref =   40.000000pF
Rref =   100.000000M
Vref =   0.0V
C_comp   8.196500pF   7.968500pF   8.492600pF
[Temperature Range]   25.000000   0.125000k   -40.000000
[Pullup Reference]   3.300000V   2.700000V   3.600000V
[Pulldown Reference]   0.0V   0.0V   0.0V
[POWER Clamp Reference]   3.300000V   2.700000V   3.600000V
[GND Clamp Reference]   0.0V   0.0V   0.0V
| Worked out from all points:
|   slope of the pulldown table from 0 to 0.495 V, typ, clamps not added: 20.1 ohm
|   slope of the pullup table from 0 to 0.495 V, typ, clamps not added: 21.8 ohm
|   GND clamp passes 1 mA (typ) near -0.52 V on its own axis
|   POWER clamp passes 1 mA (typ) near -0.81 V on its own axis
|   rising waveform, R_fixture 50.000000, V_fixture 3.300000: 20-80 % time 529ps typ, 501ps min, 532ps max; typ from 1.09 V to 3.3 V
|   rising waveform, R_fixture 50.000000, V_fixture 0.0: 20-80 % time 2.59ns typ, 2.4ns min, 2.18ns max; typ from 0 V to 2.16 V
|   falling waveform, R_fixture 50.000000, V_fixture 3.300000: 20-80 % time 2.44ns typ, 2.27ns min, 2.13ns max; typ from 3.3 V to 1.09 V
|   falling waveform, R_fixture 50.000000, V_fixture 0.0: 20-80 % time 846ps typ, 950ps min, 755ps max; typ from 2.16 V to 0 V
[Pulldown]
|Voltage   I(typ)   I(min)   I(max)
-3.3V     -38.65mA   -23.43mA   -51.3mA
-800mV    -38.65mA   -23.43mA   -49.55mA
600mV     28.88mA    17.56mA    38.65mA
1.4V      49.88mA    26.66mA    69.84mA
4.1V      56.96mA    32mA       77.99mA
4.4V      62mA       32mA       81.8mA
4.5V      100mA      32mA       83.9mA
4.7V      100mA      32mA       89mA
4.8V      100mA      32mA       100mA
5.1V      100mA      32mA       100mA
5.2V      1A         1A         100mA
6.6V      1A         1A         1A
[Pullup]
|Voltage   I(typ)   I(min)   I(max)
-3.3V     100mA      1A         67mA
-1.6V     100mA      1A         67mA
-1.5V     100mA      40mA       67mA
-1.2V     100mA      40mA       67mA
-1.1V     52mA       40mA       67mA
800mV     -33.66mA   -20.62mA   -46.63mA
2V        -56.45mA   -30.57mA   -80.98mA
3.5V      -61.24mA   -32.71mA   -88.93mA
4.2V      -62.54mA   -46.6mA    -90.53mA
4.9V      -81.9mA    -65mA      -102.4mA
5.5V      -103mA     -65mA      -126.2mA
6.6V      -103mA     -65mA      -139mA
[GND_clamp]
|Voltage   I(typ)   I(min)   I(max)
-3.3V     -9.479A    -9.465A    -9.974A
-1.2V     -2.125A    -2.854A    -1.857A
-1.13V    -1.511A    -2.236A    -1.236A
-1.06V    -933.3mA   -1.641A    -660.9mA
-990mV    -433.3mA   -1.082A    -207mA
-920mV    -110.3mA   -591mA     -31.46mA
-850mV    -19.8mA    -226.8mA   -13.66mA
-780mV    -8.323mA   -53.94mA   -9.521mA
-710mV    -5.297mA   -11.95mA   -6.277mA
-640mV    -3.244mA   -4.292mA   -3.591mA
3.28V     81.28uA    57.87uA    93.98uA
[POWER_clamp]
|Voltage   I(typ)   I(min)   I(max)
-3.28V    7.328A     6.064A     7.43A
-1.08V    7.328A     6.064A     7.43A
-1.04V    7.328A     6.064A     1.015A
-1V       1.545A     6.064A     138.6mA
-960mV    325.6mA    6.064A     18.93mA
-920mV    68.64mA    1.89A      2.585mA
-880mV    14.47mA    589mA      353uA
-840mV    3.05mA     183.6mA    105.2uA
-800mV    642.9uA    57.21mA    105.2uA
-720mV    28.59uA    5.557mA    105.2uA
0V        0A         0A         0A
[Ramp]
| variable   typ   min   max
dV/dt_r  1.28393/2.58462n   0.82050/2.38831n   1.58725/2.18727n
dV/dt_f  1.30050/2.41767n   0.78300/2.25179n   1.59746/2.12518n
R_load = 50.000000
[Rising Waveform]
R_fixture= 50.000000
V_fixture= 3.300000
V_fixture_min= 2.700000
V_fixture_max= 3.600000
|time   V(typ)   V(min)   V(max)
0s        1.09V      1.369V     914.2mV
250.2ps   1.09V      1.369V     1.024V
460.5ps   1.099V     1.369V     2.067V
540.5ps   1.138V     1.369V     2.319V
610.6ps   1.26V      1.369V     2.506V
900.9ps   2.326V     1.37V      3.1V
1.251ns   2.897V     1.471V     3.375V
1.752ns   3.158V     2.339V     3.527V
2.142ns   3.231V     2.557V     3.564V
4.985ns   3.299V     2.699V     3.599V
[Rising Waveform]
R_fixture= 50.000000
V_fixture= 0.0
V_fixture_min= 0.0
V_fixture_max= 0.0
|time   V(typ)   V(min)   V(max)
0s        34.9uV     19.61uV    -14.06uV
760.8ps   -17.13mV   32.35uV    1.998mV
1.441ns   43.9mV     -12.78mV   254mV
2.242ns   325.6mV    58.2mV     790.5mV
3.704ns   1.071V     562.9mV    1.909V
4.224ns   1.345V     756.3mV    2.22V
4.705ns   1.571V     918mV      2.398V
5.526ns   1.874V     1.138V     2.533V
6.466ns   2.036V     1.273V     2.597V
9.97ns    2.159V     1.378V     2.651V
[Falling Waveform]
R_fixture= 50.000000
V_fixture= 3.300000
V_fixture_min= 2.700000
V_fixture_max= 3.600000
|time   V(typ)   V(min)   V(max)
0s        3.299V     2.699V     3.599V
840.8ps   3.313V     2.699V     3.61V
1.341ns   3.305V     2.708V     3.441V
1.982ns   3.138V     2.703V     2.956V
2.543ns   2.829V     2.602V     2.491V
3.904ns   2.003V     2.004V     1.498V
4.625ns   1.67V      1.775V     1.175V
5.285ns   1.415V     1.62V      1.054V
6.326ns   1.231V     1.5V       981.5mV
9.97ns    1.09V      1.369V     914.2mV
[Falling Waveform]
R_fixture= 50.000000
V_fixture= 0.0
V_fixture_min= 0.0
V_fixture_max= 0.0
|time   V(typ)   V(min)   V(max)
0s        2.159V     1.378V     2.651V
250.2ps   2.161V     1.378V     2.534V
580.6ps   2.062V     1.378V     1.591V
750.8ps   1.763V     1.379V     1.119V
961ps     1.296V     1.378V     756.1mV
1.231ns   793.9mV    1.324V     477.8mV
1.522ns   494.6mV    1.068V     294mV
2.192ns   163.3mV    427.6mV    59.33mV
2.763ns   43.53mV    140.5mV    12.38mV
4.985ns   34.9uV     19.61uV    -14.06uV
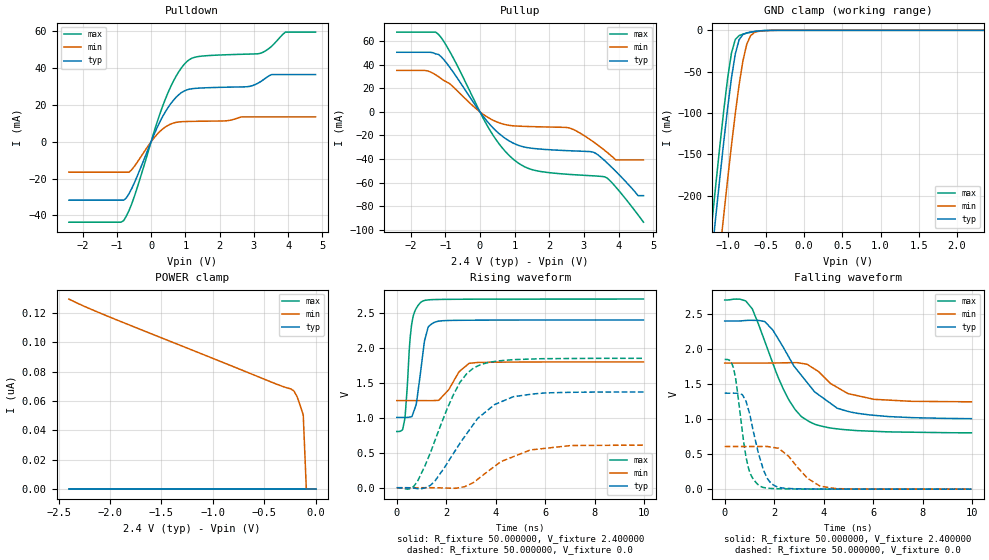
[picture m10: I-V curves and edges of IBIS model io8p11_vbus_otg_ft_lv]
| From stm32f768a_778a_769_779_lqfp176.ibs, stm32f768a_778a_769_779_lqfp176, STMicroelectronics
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|   Model io8p11_vbus_otg_ft_lv
[Model]  io8p11_vbus_otg_ft_lv
Model_type I/O
Polarity   Non-Inverting
Enable   Active-Low
Vinl =   0.720000V
Vinh =   1.680000V
Vmeas =  1.200000V
Cref =   30.000000pF
Rref =   100.000000M
Vref =   0.0V
C_comp   3.193600pF   3.100000pF   3.332100pF
[Temperature Range]   25.000000   0.125000k   -40.000000
[Pullup Reference]   2.400000V   1.800000V   2.700000V
[Pulldown Reference]   0.0V   0.0V   0.0V
[POWER Clamp Reference]   2.400000V   1.800000V   2.700000V
[GND Clamp Reference]   0.0V   0.0V   0.0V
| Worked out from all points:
|   slope of the pulldown table from 0 to 0.36 V, typ, clamps not added: 25 ohm
|   slope of the pullup table from 0 to 0.36 V, typ, clamps not added: 27.7 ohm
|   GND clamp passes 1 mA (typ) near -0.61 V on its own axis
|   rising waveform, R_fixture 50.000000, V_fixture 2.400000: 20-80 % time 312ps typ, 637ps min, 225ps max; typ from 1.01 V to 2.4 V
|   rising waveform, R_fixture 50.000000, V_fixture 0.0: 20-80 % time 1.73ns typ, 1.74ns min, 1.31ns max; typ from 0 V to 1.37 V
|   falling waveform, R_fixture 50.000000, V_fixture 2.400000: 20-80 % time 1.84ns typ, 1.32ns min, 1.36ns max; typ from 2.4 V to 1.01 V
|   falling waveform, R_fixture 50.000000, V_fixture 0.0: 20-80 % time 576ps typ, 976ps min, 435ps max; typ from 1.37 V to 0 V
[Pulldown]
|Voltage   I(typ)   I(min)   I(max)
-2.4V     -31.69mA   -16.5mA    -43.66mA
-800mV    -31.69mA   -16.5mA    -42.82mA
-480mV    -21.96mA   -13.17mA   -29.19mA
80mV      3.63mA     1.966mA    5.014mA
480mV     18.16mA    8.738mA    26.02mA
800mV     25.38mA    10.72mA    37.77mA
1.12V     28.53mA    11.02mA    44.6mA
2.8V      29.84mA    13.49mA    47.53mA
3.2V      32.65mA    13.49mA    48.05mA
3.52V     36.43mA    13.49mA    51.84mA
3.92V     36.43mA    13.49mA    59.49mA
4.8V      36.43mA    13.49mA    59.49mA
[Pullup]
|Voltage   I(typ)   I(min)   I(max)
-2.4V     50.45mA    35.08mA    67.53mA
-1.52V    50.45mA    34.74mA    67.53mA
-1.2V     48.64mA    29.87mA    65.68mA
320mV     -11.75mA   -6.207mA   -17.08mA
1.04V     -27.54mA   -11.97mA   -41.91mA
1.6V      -31.14mA   -12.58mA   -49.63mA
2.56V     -32.88mA   -13.49mA   -52.9mA
3.28V     -34.19mA   -25.52mA   -54.18mA
3.6V      -41.31mA   -32.61mA   -54.99mA
3.92V     -50.32mA   -40.7mA    -63.62mA
4.56V     -70.9mA    -40.7mA    -87.08mA
4.72V     -70.9mA    -40.7mA    -93.4mA
[GND_clamp]
|Voltage   I(typ)   I(min)   I(max)
-2.4V     -1.424A    -1.508A    -1.393A
-1.25V    -311.3mA   -401.9mA   -273.4mA
-1.2V     -265.5mA   -356.1mA   -227.3mA
-1.15V    -220.5mA   -310.9mA   -182mA
-1.1V     -176.4mA   -266.2mA   -138mA
-1.05V    -133.9mA   -222.5mA   -96.06mA
-950mV    -57.51mA   -139mA     -27.35mA
-900mV    -28.55mA   -100.5mA   -11.03mA
-850mV    -11.33mA   -65.67mA   -6.322mA
-750mV    -3.069mA   -16.69mA   -3.425mA
-600mV    -864.6uA   -1.294mA   -852.2uA
2.35V     0A         0A         0A
[POWER_clamp]
|Voltage   I(typ)   I(min)   I(max)
-2.4V     0A         129.4nA    0A
-1.98V    0A         116.5nA    0A
-390mV    0A         71.78nA    0A
-240mV    0A         68.22nA    0A
-210mV    0A         66.81nA    0A
-180mV    0A         62.95nA    0A
-120mV    0A         50.47nA    0A
-90mV     0A         0A         0A
0V        0A         0A         0A
[Ramp]
| variable   typ   min   max
dV/dt_r  0.82170/1.72716n   0.36472/1.74097n   1.11108/1.30618n
dV/dt_f  0.83274/1.83229n   0.33252/1.34346n   1.13578/1.35708n
R_load = 50.000000
[Rising Waveform]
R_fixture= 50.000000
V_fixture= 2.400000
V_fixture_min= 1.800000
V_fixture_max= 2.700000
|time   V(typ)   V(min)   V(max)
0s        1.006V     1.247V     804.6mV
320.3ps   1.006V     1.247V     976.8mV
540.5ps   1.012V     1.247V     2.146V
620.6ps   1.025V     1.247V     2.375V
800.8ps   1.226V     1.247V     2.576V
1.041ns   1.881V     1.247V     2.669V
1.281ns   2.305V     1.246V     2.688V
1.682ns   2.383V     1.25V      2.694V
2.923ns   2.397V     1.78V      2.697V
9.97ns    2.4V       1.8V       2.699V
[Rising Waveform]
R_fixture= 50.000000
V_fixture= 0.0
V_fixture_min= 0.0
V_fixture_max= 0.0
|time   V(typ)   V(min)   V(max)
0s        170.9uV    66.43uV    495.2uV
560.6ps   -1.97mV    49.03uV    -9.895mV
840.8ps   -12.99mV   52.8uV     94.02mV
1.361ns   34.84mV    86.1uV     504.6mV
2.282ns   486.5mV    -7.377mV   1.326V
2.563ns   642.1mV    3.665mV    1.512V
3.123ns   919.9mV    79.21mV    1.717V
3.964ns   1.192V     308.5mV    1.807V
5.405ns   1.337V     540.9mV    1.841V
9.97ns    1.37V      609mV      1.852V
[Falling Waveform]
R_fixture= 50.000000
V_fixture= 2.400000
V_fixture_min= 1.800000
V_fixture_max= 2.700000
|time   V(typ)   V(min)   V(max)
0s        2.4V       1.8V       2.699V
840.8ps   2.407V     1.8V       2.688V
1.101ns   2.41V      1.8V       2.58V
1.622ns   2.391V     1.8V       2.108V
2.382ns   2.015V     1.803V     1.419V
2.843ns   1.737V     1.805V     1.138V
3.423ns   1.482V     1.761V     962.9mV
4.545ns   1.156V     1.453V     860.7mV
5.005ns   1.108V     1.362V     845.3mV
9.97ns    1.006V     1.247V     804.6mV
[Falling Waveform]
R_fixture= 50.000000
V_fixture= 0.0
V_fixture_min= 0.0
V_fixture_max= 0.0
|time   V(typ)   V(min)   V(max)
0s        1.37V      609mV      1.852V
240.2ps   1.37V      609mV      1.832V
360.4ps   1.37V      609mV      1.724V
860.9ps   1.257V     608.9mV    459.4mV
1.041ns   1.021V     608.7mV    215.5mV
1.441ns   419.2mV    608.9mV    40.55mV
1.722ns   153.8mV    608.8mV    13.85mV
2.042ns   44.92mV    591mV      7.126mV
3.864ns   2.164mV    42.02mV    1.34mV
9.97ns    170.9uV    66.43uV    495.2uV
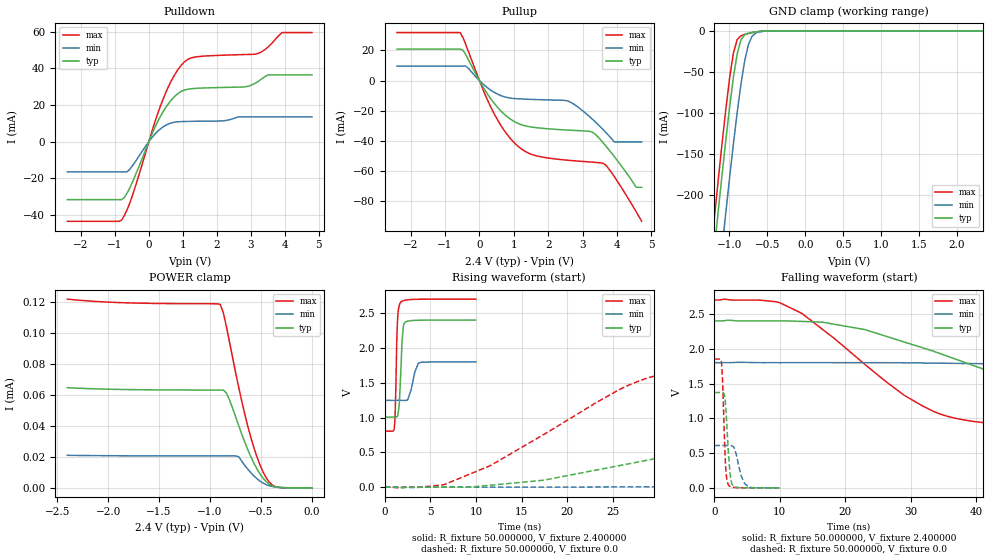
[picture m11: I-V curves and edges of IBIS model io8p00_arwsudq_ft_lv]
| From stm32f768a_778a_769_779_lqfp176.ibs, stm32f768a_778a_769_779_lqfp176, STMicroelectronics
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|   Model io8p00_arwsudq_ft_lv
[Model]  io8p00_arwsudq_ft_lv
Model_type I/O
Polarity   Non-Inverting
Enable   Active-Low
Vinl =   0.720000V
Vinh =   1.680000V
Vmeas =  1.200000V
Cref =   50.000000pF
Rref =   100.000000M
Vref =   0.0V
C_comp   2.828000pF   2.774600pF   2.917100pF
[Temperature Range]   25.000000   0.125000k   -40.000000
[Pullup Reference]   2.400000V   1.800000V   2.700000V
[Pulldown Reference]   0.0V   0.0V   0.0V
[POWER Clamp Reference]   2.400000V   1.800000V   2.700000V
[GND Clamp Reference]   0.0V   0.0V   0.0V
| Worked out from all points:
|   slope of the pulldown table from 0 to 0.36 V, typ, clamps not added: 25 ohm
|   slope of the pullup table from 0 to 0.36 V, typ, clamps not added: 27.7 ohm
|   GND clamp passes 1 mA (typ) near -0.62 V on its own axis
|   rising waveform, R_fixture 50.000000, V_fixture 2.400000: 20-80 % time 289ps typ, 617ps min, 206ps max; typ from 1.01 V to 2.4 V
|   rising waveform, R_fixture 50.000000, V_fixture 0.0: 20-80 % time 30.9ns typ, 80.9ns min, 14.7ns max; typ from 0 V to 1.37 V
|   falling waveform, R_fixture 50.000000, V_fixture 2.400000: 20-80 % time 29.2ns typ, 75.7ns min, 15.8ns max; typ from 2.4 V to 1.01 V
|   falling waveform, R_fixture 50.000000, V_fixture 0.0: 20-80 % time 542ps typ, 1ns min, 412ps max; typ from 1.37 V to 0 V
[Pulldown]
|Voltage   I(typ)   I(min)   I(max)
-2.4V     -31.67mA   -16.51mA   -43.52mA
-800mV    -31.67mA   -16.51mA   -42.87mA
-480mV    -21.98mA   -13.17mA   -29.21mA
80mV      3.63mA     1.966mA    5.013mA
480mV     18.16mA    8.738mA    26.02mA
800mV     25.38mA    10.72mA    37.77mA
1.12V     28.53mA    11.02mA    44.6mA
2.8V      29.84mA    13.5mA     47.53mA
3.2V      32.66mA    13.5mA     48.04mA
3.52V     36.46mA    13.5mA     51.85mA
3.92V     36.46mA    13.5mA     59.54mA
4.8V      36.46mA    13.5mA     59.54mA
[Pullup]
|Voltage   I(typ)   I(min)   I(max)
-2.4V     20.89mA    9.661mA    31.89mA
-560mV    20.89mA    9.661mA    31.89mA
-400mV    17.28mA    9.661mA    24.06mA
320mV     -11.75mA   -6.207mA   -17.08mA
960mV     -26.47mA   -11.82mA   -40.02mA
1.52V     -30.88mA   -12.51mA   -49.05mA
2.56V     -32.88mA   -13.49mA   -52.9mA
3.28V     -34.2mA    -25.52mA   -54.18mA
3.6V      -41.33mA   -32.62mA   -54.99mA
3.92V     -50.34mA   -40.8mA    -63.66mA
4.56V     -70.9mA    -40.8mA    -87.12mA
4.72V     -70.9mA    -40.8mA    -93.5mA
[GND_clamp]
|Voltage   I(typ)   I(min)   I(max)
-2.4V     -1.425A    -1.509A    -1.395A
-1.25V    -311.8mA   -402mA     -274.5mA
-1.2V     -266mA     -356.2mA   -228.4mA
-1.15V    -220.9mA   -310.9mA   -183.1mA
-1.1V     -176.9mA   -266.3mA   -139mA
-1.05V    -134.3mA   -222.6mA   -97.01mA
-950mV    -57.81mA   -139.1mA   -27.86mA
-900mV    -28.73mA   -100.5mA   -11.04mA
-850mV    -11.29mA   -65.69mA   -6.054mA
-750mV    -2.852mA   -16.6mA    -3.179mA
-600mV    -750uA     -1.167mA   -738.5uA
2.35V     0A         0A         0A
[POWER_clamp]
|Voltage   I(typ)   I(min)   I(max)
-2.4V     64.71uA    21.03uA    121.9uA
-1.86V    63.55uA    20.74uA    119.6uA
-900mV    63.18uA    20.63uA    118.5uA
-870mV    63.14uA    20.63uA    113.2uA
-840mV    61.36uA    20.62uA    104.3uA
-720mV    40.37uA    20.18uA    65.28uA
-630mV    24.69uA    12.08uA    39.85uA
-540mV    12.26uA    5.907uA    20uA
-480mV    6.236uA    3.061uA    10.23uA
-420mV    2.4uA      1.365uA    3.726uA
-360mV    667.9nA    564nA      839.6nA
0V        0A         0A         0A
[Ramp]
| variable   typ   min   max
dV/dt_r  0.82320/30.88957n   0.36251/83.25372n   1.11089/14.64217n
dV/dt_f  0.83664/29.19973n   0.32676/76.04111n   1.13723/15.73838n
R_load = 50.000000
[Rising Waveform]
R_fixture= 50.000000
V_fixture= 2.400000
V_fixture_min= 1.800000
V_fixture_max= 2.700000
|time   V(typ)   V(min)   V(max)
0s        1.006V     1.247V     804.6mV
1.041ns   1.006V     1.247V     831mV
1.141ns   1.006V     1.247V     1.029V
1.401ns   1.017V     1.247V     2.389V
1.582ns   1.173V     1.247V     2.606V
1.742ns   1.597V     1.247V     2.654V
2.042ns   2.309V     1.246V     2.678V
2.262ns   2.37V      1.246V     2.685V
3.684ns   2.397V     1.781V     2.698V
9.97ns    2.4V       1.8V       2.7V
[Rising Waveform]
R_fixture= 50.000000
V_fixture= 0.0
V_fixture_min= 0.0
V_fixture_max= 0.0
|time   V(typ)   V(min)   V(max)
0s        1.441uV    366.9nV    16.22uV
6.507ns   623.5uV    -75.01uV   36.33mV
11.51ns   27.28mV    -48.49uV   306.4mV
25.53ns   305.5mV    4.184mV    1.39V
28.53ns   381.4mV    5.787mV    1.556V
40.54ns   739.6mV    34.19mV    1.777V
59.56ns   1.167V     93.7mV     1.835V
81.08ns   1.319V     199.1mV    1.851V
148.1ns   1.368V     493.6mV    1.852V
249.2ns   1.37V      609.1mV    1.852V
[Falling Waveform]
R_fixture= 50.000000
V_fixture= 2.400000
V_fixture_min= 1.800000
V_fixture_max= 2.700000
|time   V(typ)   V(min)   V(max)
0s        2.4V       1.8V       2.7V
10.01ns   2.4V       1.8V       2.661V
13.51ns   2.392V     1.8V       2.5V
23.02ns   2.275V     1.799V     1.775V
32.03ns   2.008V     1.795V     1.168V
44.04ns   1.612V     1.782V     910.6mV
61.06ns   1.229V     1.717V     846mV
88.59ns   1.07V      1.555V     816.5mV
145.1ns   1.015V     1.346V     805.1mV
249.2ns   1.006V     1.247V     804.6mV
[Falling Waveform]
R_fixture= 50.000000
V_fixture= 0.0
V_fixture_min= 0.0
V_fixture_max= 0.0
|time   V(typ)   V(min)   V(max)
0s        1.37V      609.1mV    1.852V
1.061ns   1.37V      609.1mV    1.822V
1.261ns   1.37V      609mV      1.542V
1.682ns   1.241V     608.8mV    391.9mV
1.862ns   990.4mV    608.5mV    155.5mV
2.142ns   529mV      608.7mV    47.21mV
2.503ns   138.4mV    611.1mV    14.57mV
2.983ns   20.87mV    585.8mV    5.39mV
4.645ns   1.685mV    61.04mV    1.138mV
9.97ns    1.441uV    366.9nV    16.22uV
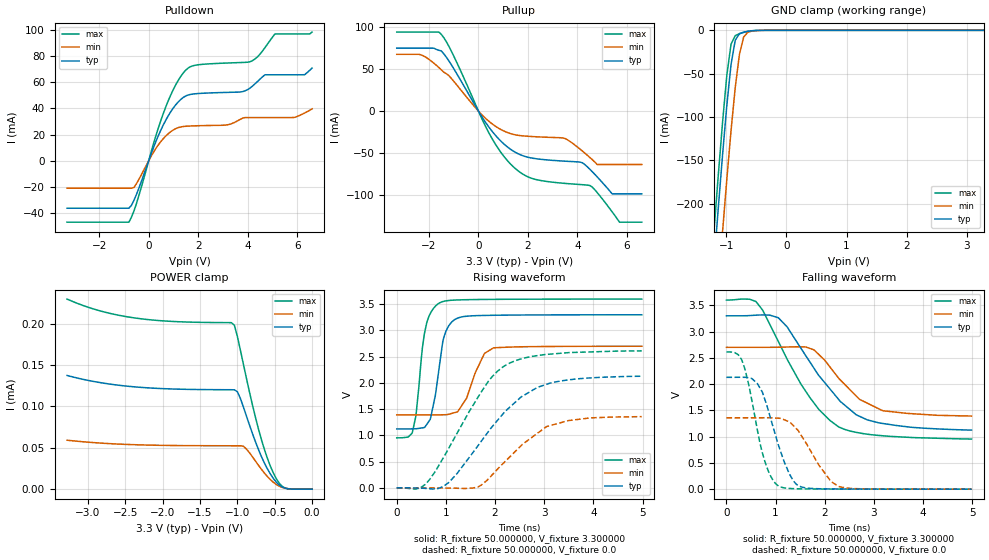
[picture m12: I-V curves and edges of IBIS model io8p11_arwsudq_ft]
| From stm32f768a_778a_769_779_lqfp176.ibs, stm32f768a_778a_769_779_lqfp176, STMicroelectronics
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|   Model io8p11_arwsudq_ft
[Model]  io8p11_arwsudq_ft
Model_type I/O
Polarity   Non-Inverting
Enable   Active-Low
Vinl =   0.990000V
Vinh =   2.310000V
Vmeas =  1.650000V
Cref =   30.000000pF
Rref =   100.000000M
Vref =   0.0V
C_comp   2.905500pF   2.831700pF   2.987900pF
[Temperature Range]   25.000000   0.125000k   -40.000000
[Pullup Reference]   3.300000V   2.700000V   3.600000V
[Pulldown Reference]   0.0V   0.0V   0.0V
[POWER Clamp Reference]   3.300000V   2.700000V   3.600000V
[GND Clamp Reference]   0.0V   0.0V   0.0V
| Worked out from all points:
|   slope of the pulldown table from 0 to 0.495 V, typ, clamps not added: 20.9 ohm
|   slope of the pullup table from 0 to 0.495 V, typ, clamps not added: 22.6 ohm
|   GND clamp passes 1 mA (typ) near -0.62 V on its own axis
|   rising waveform, R_fixture 50.000000, V_fixture 3.300000: 20-80 % time 217ps typ, 339ps min, 191ps max; typ from 1.12 V to 3.3 V
|   rising waveform, R_fixture 50.000000, V_fixture 0.0: 20-80 % time 1.14ns typ, 964ps min, 998ps max; typ from 0 V to 2.13 V
|   falling waveform, R_fixture 50.000000, V_fixture 3.300000: 20-80 % time 1.07ns typ, 815ps min, 999ps max; typ from 3.3 V to 1.12 V
|   falling waveform, R_fixture 50.000000, V_fixture 0.0: 20-80 % time 435ps typ, 549ps min, 356ps max; typ from 2.13 V to 0 V
[Pulldown]
|Voltage   I(typ)   I(min)   I(max)
-3.3V     -36.4mA    -21.08mA   -47.09mA
-800mV    -36.4mA    -21.08mA   -47.09mA
-600mV    -30.5mA    -20.54mA   -38.69mA
700mV     31.4mA     19.11mA    41.71mA
1.2V      45.15mA    25.37mA    61.75mA
1.6V      50.35mA    26.5mA     71.06mA
3.1V      52.28mA    27.26mA    74.76mA
4.1V      55.71mA    33.04mA    75.8mA
4.7V      65.81mA    33.04mA    86.69mA
5.1V      65.81mA    33.04mA    97.04mA
6.3V      65.87mA    36.5mA     97.04mA
6.6V      70.93mA    39.72mA    98.49mA
[Pullup]
|Voltage   I(typ)   I(min)   I(max)
-3.3V     74.74mA    67.41mA    93.8mA
-2.3V     74.74mA    66.57mA    93.8mA
-1.5V     71.48mA    49mA       91.17mA
500mV     -22.07mA   -14mA      -30.03mA
1.6V      -50.64mA   -28.81mA   -70.96mA
3.5V      -59.53mA   -32.66mA   -85.92mA
4.2V      -61.44mA   -47.49mA   -87.46mA
4.5V      -69.08mA   -55.13mA   -88.39mA
4.8V      -78.23mA   -63.5mA    -96.88mA
5.4V      -98.3mA    -63.5mA    -119.6mA
5.7V      -98.3mA    -63.5mA    -132mA
6.6V      -98.3mA    -63.5mA    -132mA
[GND_clamp]
|Voltage   I(typ)   I(min)   I(max)
-3.3V     -2.317A    -2.396A    -2.29A
-1.2V     -266mA     -356.2mA   -228.4mA
-1.13V    -203.2mA   -293mA     -165.3mA
-1.06V    -142.7mA   -231.3mA   -105.2mA
-990mV    -86.51mA   -171.7mA   -51.78mA
-920mV    -39.3mA    -115.7mA   -15.93mA
-850mV    -11.37mA   -65.76mA   -6.097mA
-780mV    -3.83mA    -27.55mA   -3.88mA
-710mV    -2.09mA    -7.747mA   -2.382mA
-640mV    -1.147mA   -2.129mA   -1.22mA
-570mV    -523.9uA   -800uA     -476.9uA
3.28V     0A         0A         0A
[POWER_clamp]
|Voltage   I(typ)   I(min)   I(max)
-3.28V    137.3uA    59.14uA    229.6uA
-2.36V    123.4uA    53.65uA    206.6uA
-1.08V    120.1uA    52.41uA    201.1uA
-1.04V    120uA      52.41uA    198uA
-1V       117.7uA    52.4uA     184.5uA
-920mV    99.46uA    51.91uA    151.2uA
-720mV    48.42uA    29.12uA    73.51uA
-600mV    24.82uA    15.47uA    37.72uA
-520mV    13.1uA     8.45uA     19.84uA
-440mV    5.058uA    3.61uA     7.276uA
-360mV    1.193uA    1.129uA    1.311uA
0V        0A         0A         0A
[Ramp]
| variable   typ   min   max
dV/dt_r  1.26018/1.13309n   0.80370/0.95448n   1.56023/0.99574n
dV/dt_f  1.27554/1.04783n   0.76776/0.78816n   1.56946/0.99113n
R_load = 50.000000
[Rising Waveform]
R_fixture= 50.000000
V_fixture= 3.300000
V_fixture_min= 2.700000
V_fixture_max= 3.600000
|time   V(typ)   V(min)   V(max)
0s        1.124V     1.392V     954.3mV
320.3ps   1.126V     1.392V     1.068V
390.4ps   1.128V     1.392V     1.377V
570.6ps   1.157V     1.392V     2.975V
690.7ps   1.339V     1.391V     3.337V
870.9ps   2.345V     1.393V     3.526V
961ps     2.877V     1.395V     3.557V
1.131ns   3.173V     1.423V     3.577V
1.972ns   3.29V      2.67V      3.593V
4.985ns   3.3V       2.7V       3.599V
[Rising Waveform]
R_fixture= 50.000000
V_fixture= 0.0
V_fixture_min= 0.0
V_fixture_max= 0.0
|time   V(typ)   V(min)   V(max)
0s        349.9uV    197.2uV    636.1uV
480.5ps   -3.157mV   140.6uV    1.805mV
670.7ps   -15.45mV   180.8uV    162.5mV
961ps     36.4mV     -1.108mV   596.3mV
1.662ns   816.4mV    23.2mV     1.742V
1.932ns   1.157V     239.6mV    2.111V
2.242ns   1.491V     539mV      2.353V
3.053ns   1.977V     1.171V     2.545V
3.934ns   2.097V     1.334V     2.592V
4.985ns   2.129V     1.359V     2.612V
[Falling Waveform]
R_fixture= 50.000000
V_fixture= 3.300000
V_fixture_min= 2.700000
V_fixture_max= 3.600000
|time   V(typ)   V(min)   V(max)
0s        3.3V       2.7V       3.599V
600.6ps   3.312V     2.7V       3.57V
740.7ps   3.316V     2.7V       3.399V
1.051ns   3.264V     2.701V     2.819V
1.512ns   2.686V     2.708V     2.006V
1.782ns   2.3V       2.65V      1.639V
2.282ns   1.709V     2.112V     1.185V
2.643ns   1.414V     1.77V      1.081V
3.183ns   1.25V      1.492V     1.016V
4.985ns   1.124V     1.392V     954.3mV
[Falling Waveform]
R_fixture= 50.000000
V_fixture= 0.0
V_fixture_min= 0.0
V_fixture_max= 0.0
|time   V(typ)   V(min)   V(max)
0s        2.129V     1.359V     2.612V
310.3ps   2.129V     1.359V     2.463V
460.5ps   2.117V     1.358V     1.96V
630.6ps   2.008V     1.358V     1.119V
850.9ps   1.501V     1.36V      346.8mV
1.061ns   829.3mV    1.35V      60.38mV
1.421ns   94.61mV    1.152V     8.253mV
1.882ns   8.138mV    456.1mV    3.649mV
2.292ns   3.58mV     48.5mV     2.5mV
4.985ns   349.9uV    197.2uV    636.1uV
